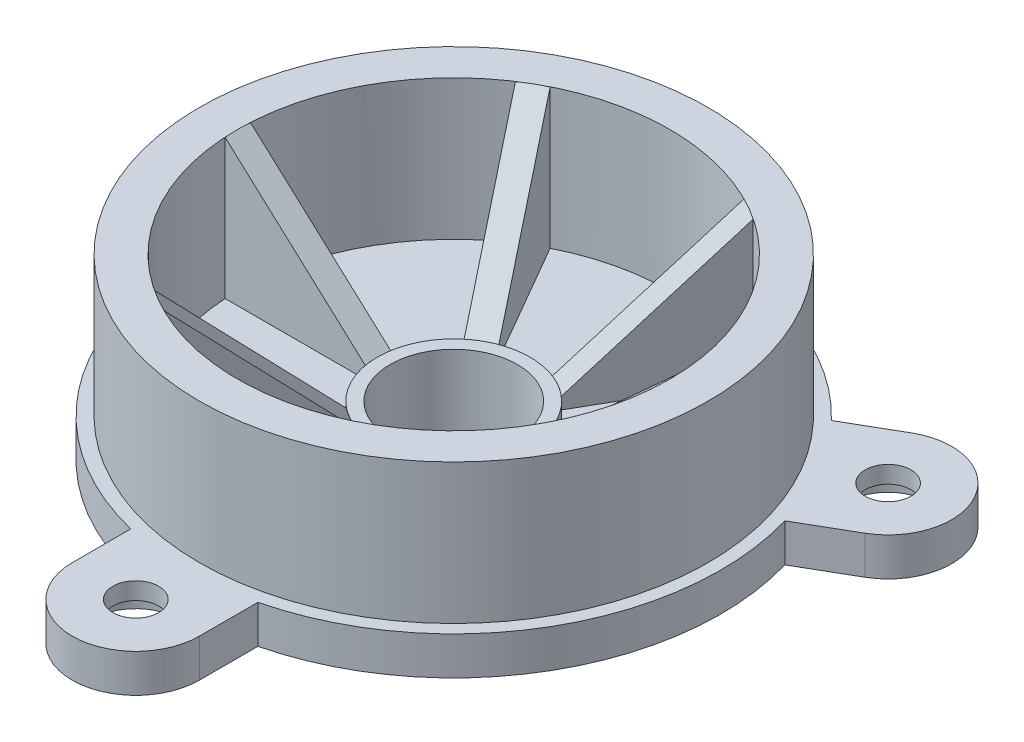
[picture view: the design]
ISO-10303-21;
HEADER;
FILE_DESCRIPTION(('STEP AP214'),'2;1');
FILE_NAME('part.step','',(''),(''),'','','');
FILE_SCHEMA(('AUTOMOTIVE_DESIGN { 1 0 10303 214 1 1 1 1 }'));
ENDSEC;
DATA;
#1=APPLICATION_CONTEXT('core data for automotive mechanical design processes');
#2=APPLICATION_PROTOCOL_DEFINITION('international standard','automotive_design',2000,#1);
#3=PRODUCT_CONTEXT('',#1,'mechanical');
#4=PRODUCT('Part','Part','',(#3));
#5=PRODUCT_RELATED_PRODUCT_CATEGORY('part','',(#4));
#6=PRODUCT_DEFINITION_FORMATION('','',#4);
#7=PRODUCT_DEFINITION_CONTEXT('part definition',#1,'design');
#8=PRODUCT_DEFINITION('design','',#6,#7);
#9=PRODUCT_DEFINITION_SHAPE('','',#8);
#10=(LENGTH_UNIT() NAMED_UNIT(*) SI_UNIT(.MILLI.,.METRE.));
#11=(NAMED_UNIT(*) PLANE_ANGLE_UNIT() SI_UNIT($,.RADIAN.));
#12=(NAMED_UNIT(*) SI_UNIT($,.STERADIAN.) SOLID_ANGLE_UNIT());
#13=UNCERTAINTY_MEASURE_WITH_UNIT(LENGTH_MEASURE(1.E-05),#10,'distance_accuracy_value','');
#14=(GEOMETRIC_REPRESENTATION_CONTEXT(3) GLOBAL_UNCERTAINTY_ASSIGNED_CONTEXT((#13)) GLOBAL_UNIT_ASSIGNED_CONTEXT((#10,
#11,#12)) REPRESENTATION_CONTEXT('',''));
#15=CARTESIAN_POINT('',(0.,0.,0.));
#16=DIRECTION('',(0.,0.,1.));
#17=DIRECTION('',(1.,0.,0.));
#18=AXIS2_PLACEMENT_3D('',#15,#16,#17);
#19=CARTESIAN_POINT('',(0.,91.9242942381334,0.));
#20=DIRECTION('',(0.,1.,0.));
#21=DIRECTION('',(0.,0.,1.));
#22=AXIS2_PLACEMENT_3D('',#19,#20,#21);
#23=CYLINDRICAL_SURFACE('',#22,6.00000000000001);
#24=CARTESIAN_POINT('',(0.,0.54545454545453,0.));
#25=DIRECTION('',(-0.336336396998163,-0.739940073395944,-0.582551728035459));
#26=DIRECTION('',(-0.369970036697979,0.672672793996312,-0.640806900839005));
#27=AXIS2_PLACEMENT_3D('',#24,#25,#26);
#28=ELLIPSE('',#27,8.10876477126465,6.00000000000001);
#29=CARTESIAN_POINT('',(-3.00000000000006,6.00000000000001,-5.1961524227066));
#30=VERTEX_POINT('',#29);
#31=CARTESIAN_POINT('',(-3.82406529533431,5.92370889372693,-4.62347538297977));
#32=VERTEX_POINT('',#31);
#33=EDGE_CURVE('E50',#30,#32,#28,.F.);
#34=ORIENTED_EDGE('',*,*,#33,.T.);
#35=DIRECTION('',(0.,1.,0.));
#36=VECTOR('',#35,1.);
#37=CARTESIAN_POINT('',(-3.82406529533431,91.9242942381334,-4.62347538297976));
#38=LINE('',#37,#36);
#39=CARTESIAN_POINT('',(-3.82406529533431,5.,-4.62347538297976));
#40=VERTEX_POINT('',#39);
#41=EDGE_CURVE('E341',#32,#40,#38,.F.);
#42=ORIENTED_EDGE('',*,*,#41,.T.);
#43=CARTESIAN_POINT('',(0.,5.,0.));
#44=DIRECTION('',(0.,1.,0.));
#45=DIRECTION('',(0.,0.,1.));
#46=AXIS2_PLACEMENT_3D('',#43,#44,#45);
#47=CIRCLE('',#46,6.00000000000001);
#48=CARTESIAN_POINT('',(-5.91607978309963,5.,-1.));
#49=VERTEX_POINT('',#48);
#50=EDGE_CURVE('E617',#40,#49,#47,.T.);
#51=ORIENTED_EDGE('',*,*,#50,.T.);
#52=DIRECTION('',(0.,1.,0.));
#53=VECTOR('',#52,1.);
#54=CARTESIAN_POINT('',(-5.91607978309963,91.9242942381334,-1.));
#55=LINE('',#54,#53);
#56=CARTESIAN_POINT('',(-5.91607978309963,5.92370889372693,-1.));
#57=VERTEX_POINT('',#56);
#58=EDGE_CURVE('E466',#57,#49,#55,.F.);
#59=ORIENTED_EDGE('',*,*,#58,.F.);
#60=CARTESIAN_POINT('',(0.,0.545454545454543,0.));
#61=DIRECTION('',(-0.672672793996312,-0.739940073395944,0.));
#62=DIRECTION('',(-0.739940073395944,0.672672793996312,0.));
#63=AXIS2_PLACEMENT_3D('',#60,#61,#62);
#64=ELLIPSE('',#63,8.10876477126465,6.00000000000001);
#65=CARTESIAN_POINT('',(-6.00000000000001,6.00000000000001,0.));
#66=VERTEX_POINT('',#65);
#67=EDGE_CURVE('E479',#57,#66,#64,.F.);
#68=ORIENTED_EDGE('',*,*,#67,.T.);
#69=CARTESIAN_POINT('',(0.,6.00000000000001,0.));
#70=DIRECTION('',(0.,1.,0.));
#71=DIRECTION('',(0.,0.,1.));
#72=AXIS2_PLACEMENT_3D('',#69,#70,#71);
#73=CIRCLE('',#72,6.00000000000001);
#74=EDGE_CURVE('E622',#30,#66,#73,.T.);
#75=ORIENTED_EDGE('',*,*,#74,.F.);
#76=EDGE_LOOP('',(#34,#42,#51,#59,#68,#75));
#77=FACE_BOUND('',#76,.T.);
#78=ADVANCED_FACE('F33',(#77),#23,.T.);
#79=CARTESIAN_POINT('',(0.,91.9242942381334,0.));
#80=DIRECTION('',(0.,1.,0.));
#81=DIRECTION('',(0.,0.,1.));
#82=AXIS2_PLACEMENT_3D('',#79,#80,#81);
#83=CYLINDRICAL_SURFACE('',#82,17.);
#84=CARTESIAN_POINT('',(0.,5.,0.));
#85=DIRECTION('',(0.,1.,0.));
#86=DIRECTION('',(0.,0.,1.));
#87=AXIS2_PLACEMENT_3D('',#84,#85,#86);
#88=CIRCLE('',#87,17.);
#89=CARTESIAN_POINT('',(-9.35130677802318,5.,-14.196938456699));
#90=VERTEX_POINT('',#89);
#91=CARTESIAN_POINT('',(-16.9705627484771,5.,-1.));
#92=VERTEX_POINT('',#91);
#93=EDGE_CURVE('E316',#90,#92,#88,.T.);
#94=ORIENTED_EDGE('',*,*,#93,.F.);
#95=DIRECTION('',(0.,1.,0.));
#96=VECTOR('',#95,1.);
#97=CARTESIAN_POINT('',(-9.35130677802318,91.9242942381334,-14.196938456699));
#98=LINE('',#97,#96);
#99=CARTESIAN_POINT('',(-9.35130677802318,15.973238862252,-14.196938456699));
#100=VERTEX_POINT('',#99);
#101=EDGE_CURVE('E339',#90,#100,#98,.T.);
#102=ORIENTED_EDGE('',*,*,#101,.T.);
#103=CARTESIAN_POINT('',(0.,0.54545454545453,0.));
#104=DIRECTION('',(-0.336336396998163,-0.739940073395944,-0.582551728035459));
#105=DIRECTION('',(-0.369970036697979,0.672672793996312,-0.640806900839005));
#106=AXIS2_PLACEMENT_3D('',#103,#104,#105);
#107=ELLIPSE('',#106,22.9748335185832,17.);
#108=CARTESIAN_POINT('',(-8.50000000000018,16.,-14.7224318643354));
#109=VERTEX_POINT('',#108);
#110=EDGE_CURVE('E343',#100,#109,#107,.T.);
#111=ORIENTED_EDGE('',*,*,#110,.T.);
#112=CARTESIAN_POINT('',(0.,16.,0.));
#113=DIRECTION('',(0.,1.,0.));
#114=DIRECTION('',(0.,0.,1.));
#115=AXIS2_PLACEMENT_3D('',#112,#113,#114);
#116=CIRCLE('',#115,17.);
#117=CARTESIAN_POINT('',(-17.,16.,0.));
#118=VERTEX_POINT('',#117);
#119=EDGE_CURVE('E610',#109,#118,#116,.T.);
#120=ORIENTED_EDGE('',*,*,#119,.T.);
#121=CARTESIAN_POINT('',(0.,0.545454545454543,0.));
#122=DIRECTION('',(-0.672672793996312,-0.739940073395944,0.));
#123=DIRECTION('',(-0.739940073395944,0.672672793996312,0.));
#124=AXIS2_PLACEMENT_3D('',#121,#122,#123);
#125=ELLIPSE('',#124,22.9748335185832,17.);
#126=CARTESIAN_POINT('',(-16.9705627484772,15.973238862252,-1.));
#127=VERTEX_POINT('',#126);
#128=EDGE_CURVE('E478',#118,#127,#125,.T.);
#129=ORIENTED_EDGE('',*,*,#128,.T.);
#130=DIRECTION('',(0.,1.,0.));
#131=VECTOR('',#130,1.);
#132=CARTESIAN_POINT('',(-16.9705627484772,91.9242942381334,-1.));
#133=LINE('',#132,#131);
#134=EDGE_CURVE('E457',#92,#127,#133,.T.);
#135=ORIENTED_EDGE('',*,*,#134,.F.);
#136=EDGE_LOOP('',(#94,#102,#111,#120,#129,#135));
#137=FACE_BOUND('',#136,.T.);
#138=ADVANCED_FACE('F655',(#137),#83,.F.);
#139=CARTESIAN_POINT('',(6.00000000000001,5.,0.));
#140=DIRECTION('',(0.,-1.,0.));
#141=DIRECTION('',(0.,0.,-1.));
#142=AXIS2_PLACEMENT_3D('',#139,#140,#141);
#143=PLANE('',#142);
#144=DIRECTION('',(-0.50000000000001,0.,-0.866025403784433));
#145=VECTOR('',#144,1.);
#146=CARTESIAN_POINT('',(2.3660254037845,5.,2.09807621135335));
#147=LINE('',#146,#145);
#148=CARTESIAN_POINT('',(-2.09201448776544,5.,-5.62347538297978));
#149=VERTEX_POINT('',#148);
#150=CARTESIAN_POINT('',(-7.61925597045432,5.,-15.196938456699));
#151=VERTEX_POINT('',#150);
#152=EDGE_CURVE('E310',#149,#151,#147,.T.);
#153=ORIENTED_EDGE('',*,*,#152,.F.);
#154=CARTESIAN_POINT('',(2.09201448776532,5.,-5.62347538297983));
#155=VERTEX_POINT('',#154);
#156=EDGE_CURVE('E738',#155,#149,#47,.T.);
#157=ORIENTED_EDGE('',*,*,#156,.F.);
#158=DIRECTION('',(0.499999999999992,0.,-0.866025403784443));
#159=VECTOR('',#158,1.);
#160=CARTESIAN_POINT('',(0.633974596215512,5.,-3.09807621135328));
#161=LINE('',#160,#159);
#162=CARTESIAN_POINT('',(7.619255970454,5.,-15.1969384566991));
#163=VERTEX_POINT('',#162);
#164=EDGE_CURVE('E312',#155,#163,#161,.T.);
#165=ORIENTED_EDGE('',*,*,#164,.T.);
#166=EDGE_CURVE('E305',#163,#151,#88,.T.);
#167=ORIENTED_EDGE('',*,*,#166,.T.);
#168=EDGE_LOOP('',(#153,#157,#165,#167));
#169=FACE_BOUND('',#168,.T.);
#170=ADVANCED_FACE('F307',(#169),#143,.F.);
#171=DIRECTION('',(0.,1.,0.));
#172=VECTOR('',#171,1.);
#173=CARTESIAN_POINT('',(-2.09201448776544,91.9242942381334,-5.62347538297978));
#174=LINE('',#173,#172);
#175=CARTESIAN_POINT('',(-2.09201448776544,5.92370889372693,-5.62347538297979));
#176=VERTEX_POINT('',#175);
#177=EDGE_CURVE('E58',#176,#149,#174,.F.);
#178=ORIENTED_EDGE('',*,*,#177,.F.);
#179=EDGE_CURVE('E345',#176,#30,#28,.F.);
#180=ORIENTED_EDGE('',*,*,#179,.T.);
#181=CARTESIAN_POINT('',(2.99999999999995,6.00000000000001,-5.19615242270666));
#182=VERTEX_POINT('',#181);
#183=EDGE_CURVE('E816',#182,#30,#73,.T.);
#184=ORIENTED_EDGE('',*,*,#183,.F.);
#185=CARTESIAN_POINT('',(0.,0.54545454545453,0.));
#186=DIRECTION('',(0.336336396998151,-0.739940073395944,-0.582551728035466));
#187=DIRECTION('',(0.369970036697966,0.672672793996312,-0.640806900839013));
#188=AXIS2_PLACEMENT_3D('',#185,#186,#187);
#189=ELLIPSE('',#188,8.10876477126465,6.00000000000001);
#190=CARTESIAN_POINT('',(2.09201448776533,5.92370889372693,-5.62347538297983));
#191=VERTEX_POINT('',#190);
#192=EDGE_CURVE('E372',#182,#191,#189,.F.);
#193=ORIENTED_EDGE('',*,*,#192,.T.);
#194=DIRECTION('',(0.,1.,0.));
#195=VECTOR('',#194,1.);
#196=CARTESIAN_POINT('',(2.09201448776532,91.9242942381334,-5.62347538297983));
#197=LINE('',#196,#195);
#198=EDGE_CURVE('E365',#191,#155,#197,.F.);
#199=ORIENTED_EDGE('',*,*,#198,.T.);
#200=ORIENTED_EDGE('',*,*,#156,.T.);
#201=EDGE_LOOP('',(#178,#180,#184,#193,#199,#200));
#202=FACE_BOUND('',#201,.T.);
#203=ADVANCED_FACE('F657',(#202),#23,.T.);
#204=CARTESIAN_POINT('',(8.49999999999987,16.,-14.7224318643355));
#205=VERTEX_POINT('',#204);
#206=EDGE_CURVE('E827',#205,#109,#116,.T.);
#207=ORIENTED_EDGE('',*,*,#206,.T.);
#208=CARTESIAN_POINT('',(-7.61925597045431,15.9732388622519,-15.196938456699));
#209=VERTEX_POINT('',#208);
#210=EDGE_CURVE('E323',#109,#209,#107,.T.);
#211=ORIENTED_EDGE('',*,*,#210,.T.);
#212=DIRECTION('',(0.,1.,0.));
#213=VECTOR('',#212,1.);
#214=CARTESIAN_POINT('',(-7.61925597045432,91.9242942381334,-15.196938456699));
#215=LINE('',#214,#213);
#216=EDGE_CURVE('E319',#151,#209,#215,.T.);
#217=ORIENTED_EDGE('',*,*,#216,.F.);
#218=ORIENTED_EDGE('',*,*,#166,.F.);
#219=DIRECTION('',(0.,1.,0.));
#220=VECTOR('',#219,1.);
#221=CARTESIAN_POINT('',(7.619255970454,91.9242942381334,-15.1969384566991));
#222=LINE('',#221,#220);
#223=CARTESIAN_POINT('',(7.619255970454,15.973238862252,-15.1969384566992));
#224=VERTEX_POINT('',#223);
#225=EDGE_CURVE('E363',#163,#224,#222,.T.);
#226=ORIENTED_EDGE('',*,*,#225,.T.);
#227=CARTESIAN_POINT('',(0.,0.54545454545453,0.));
#228=DIRECTION('',(0.336336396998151,-0.739940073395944,-0.582551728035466));
#229=DIRECTION('',(0.369970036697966,0.672672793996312,-0.640806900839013));
#230=AXIS2_PLACEMENT_3D('',#227,#228,#229);
#231=ELLIPSE('',#230,22.9748335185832,17.);
#232=EDGE_CURVE('E367',#224,#205,#231,.T.);
#233=ORIENTED_EDGE('',*,*,#232,.T.);
#234=EDGE_LOOP('',(#207,#211,#217,#218,#226,#233));
#235=FACE_BOUND('',#234,.T.);
#236=ADVANCED_FACE('F321',(#235),#83,.F.);
#237=DIRECTION('',(0.499999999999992,0.,-0.866025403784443));
#238=VECTOR('',#237,1.);
#239=CARTESIAN_POINT('',(2.3660254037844,5.,-2.0980762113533));
#240=LINE('',#239,#238);
#241=CARTESIAN_POINT('',(3.82406529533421,5.,-4.62347538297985));
#242=VERTEX_POINT('',#241);
#243=CARTESIAN_POINT('',(9.35130677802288,5.,-14.1969384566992));
#244=VERTEX_POINT('',#243);
#245=EDGE_CURVE('E350',#242,#244,#240,.T.);
#246=ORIENTED_EDGE('',*,*,#245,.F.);
#247=CARTESIAN_POINT('',(5.91607978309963,5.,-1.));
#248=VERTEX_POINT('',#247);
#249=EDGE_CURVE('E718',#248,#242,#47,.T.);
#250=ORIENTED_EDGE('',*,*,#249,.F.);
#251=DIRECTION('',(1.,0.,0.));
#252=VECTOR('',#251,1.);
#253=CARTESIAN_POINT('',(6.00000000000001,5.,-1.));
#254=LINE('',#253,#252);
#255=CARTESIAN_POINT('',(16.9705627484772,5.,-1.));
#256=VERTEX_POINT('',#255);
#257=EDGE_CURVE('E388',#248,#256,#254,.T.);
#258=ORIENTED_EDGE('',*,*,#257,.T.);
#259=EDGE_CURVE('E315',#256,#244,#88,.T.);
#260=ORIENTED_EDGE('',*,*,#259,.T.);
#261=EDGE_LOOP('',(#246,#250,#258,#260));
#262=FACE_BOUND('',#261,.T.);
#263=ADVANCED_FACE('F704',(#262),#143,.F.);
#264=DIRECTION('',(0.,1.,0.));
#265=VECTOR('',#264,1.);
#266=CARTESIAN_POINT('',(3.82406529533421,91.9242942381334,-4.62347538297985));
#267=LINE('',#266,#265);
#268=CARTESIAN_POINT('',(3.82406529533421,5.92370889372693,-4.62347538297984));
#269=VERTEX_POINT('',#268);
#270=EDGE_CURVE('E359',#269,#242,#267,.F.);
#271=ORIENTED_EDGE('',*,*,#270,.F.);
#272=EDGE_CURVE('E370',#269,#182,#189,.F.);
#273=ORIENTED_EDGE('',*,*,#272,.T.);
#274=CARTESIAN_POINT('',(6.,6.00000000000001,0.));
#275=VERTEX_POINT('',#274);
#276=EDGE_CURVE('E815',#275,#182,#73,.T.);
#277=ORIENTED_EDGE('',*,*,#276,.F.);
#278=CARTESIAN_POINT('',(0.,0.545454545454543,0.));
#279=DIRECTION('',(0.672672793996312,-0.739940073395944,0.));
#280=DIRECTION('',(0.739940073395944,0.672672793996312,0.));
#281=AXIS2_PLACEMENT_3D('',#278,#279,#280);
#282=ELLIPSE('',#281,8.10876477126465,6.00000000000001);
#283=CARTESIAN_POINT('',(5.91607978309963,5.92370889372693,-1.));
#284=VERTEX_POINT('',#283);
#285=EDGE_CURVE('E399',#275,#284,#282,.F.);
#286=ORIENTED_EDGE('',*,*,#285,.T.);
#287=DIRECTION('',(0.,1.,0.));
#288=VECTOR('',#287,1.);
#289=CARTESIAN_POINT('',(5.91607978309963,91.9242942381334,-1.));
#290=LINE('',#289,#288);
#291=EDGE_CURVE('E392',#284,#248,#290,.F.);
#292=ORIENTED_EDGE('',*,*,#291,.T.);
#293=ORIENTED_EDGE('',*,*,#249,.T.);
#294=EDGE_LOOP('',(#271,#273,#277,#286,#292,#293));
#295=FACE_BOUND('',#294,.T.);
#296=ADVANCED_FACE('F668',(#295),#23,.T.);
#297=CARTESIAN_POINT('',(17.,16.,0.));
#298=VERTEX_POINT('',#297);
#299=EDGE_CURVE('E731',#298,#205,#116,.T.);
#300=ORIENTED_EDGE('',*,*,#299,.T.);
#301=CARTESIAN_POINT('',(9.35130677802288,15.973238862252,-14.1969384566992));
#302=VERTEX_POINT('',#301);
#303=EDGE_CURVE('E369',#205,#302,#231,.T.);
#304=ORIENTED_EDGE('',*,*,#303,.T.);
#305=DIRECTION('',(0.,1.,0.));
#306=VECTOR('',#305,1.);
#307=CARTESIAN_POINT('',(9.35130677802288,91.9242942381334,-14.1969384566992));
#308=LINE('',#307,#306);
#309=EDGE_CURVE('E356',#244,#302,#308,.T.);
#310=ORIENTED_EDGE('',*,*,#309,.F.);
#311=ORIENTED_EDGE('',*,*,#259,.F.);
#312=DIRECTION('',(0.,1.,0.));
#313=VECTOR('',#312,1.);
#314=CARTESIAN_POINT('',(16.9705627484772,91.9242942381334,-1.));
#315=LINE('',#314,#313);
#316=CARTESIAN_POINT('',(16.9705627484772,15.9732388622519,-1.));
#317=VERTEX_POINT('',#316);
#318=EDGE_CURVE('E390',#256,#317,#315,.T.);
#319=ORIENTED_EDGE('',*,*,#318,.T.);
#320=CARTESIAN_POINT('',(0.,0.545454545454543,0.));
#321=DIRECTION('',(0.672672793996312,-0.739940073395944,0.));
#322=DIRECTION('',(0.739940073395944,0.672672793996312,0.));
#323=AXIS2_PLACEMENT_3D('',#320,#321,#322);
#324=ELLIPSE('',#323,22.9748335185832,17.);
#325=EDGE_CURVE('E394',#317,#298,#324,.T.);
#326=ORIENTED_EDGE('',*,*,#325,.T.);
#327=EDGE_LOOP('',(#300,#304,#310,#311,#319,#326));
#328=FACE_BOUND('',#327,.T.);
#329=ADVANCED_FACE('F702',(#328),#83,.F.);
#330=DIRECTION('',(1.,0.,0.));
#331=VECTOR('',#330,1.);
#332=CARTESIAN_POINT('',(6.00000000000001,5.,1.));
#333=LINE('',#332,#331);
#334=CARTESIAN_POINT('',(5.91607978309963,5.,1.));
#335=VERTEX_POINT('',#334);
#336=CARTESIAN_POINT('',(16.9705627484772,5.,1.));
#337=VERTEX_POINT('',#336);
#338=EDGE_CURVE('E376',#335,#337,#333,.T.);
#339=ORIENTED_EDGE('',*,*,#338,.F.);
#340=CARTESIAN_POINT('',(3.82406529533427,5.,4.62347538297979));
#341=VERTEX_POINT('',#340);
#342=EDGE_CURVE('E739',#341,#335,#47,.T.);
#343=ORIENTED_EDGE('',*,*,#342,.F.);
#344=DIRECTION('',(0.500000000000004,0.,0.866025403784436));
#345=VECTOR('',#344,1.);
#346=CARTESIAN_POINT('',(2.36602540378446,5.,2.09807621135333));
#347=LINE('',#346,#345);
#348=CARTESIAN_POINT('',(9.35130677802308,5.,14.196938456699));
#349=VERTEX_POINT('',#348);
#350=EDGE_CURVE('E415',#341,#349,#347,.T.);
#351=ORIENTED_EDGE('',*,*,#350,.T.);
#352=EDGE_CURVE('E780',#349,#337,#88,.T.);
#353=ORIENTED_EDGE('',*,*,#352,.T.);
#354=EDGE_LOOP('',(#339,#343,#351,#353));
#355=FACE_BOUND('',#354,.T.);
#356=ADVANCED_FACE('F694',(#355),#143,.F.);
#357=DIRECTION('',(0.,1.,0.));
#358=VECTOR('',#357,1.);
#359=CARTESIAN_POINT('',(5.91607978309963,91.9242942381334,1.));
#360=LINE('',#359,#358);
#361=CARTESIAN_POINT('',(5.91607978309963,5.92370889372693,1.));
#362=VERTEX_POINT('',#361);
#363=EDGE_CURVE('E385',#362,#335,#360,.F.);
#364=ORIENTED_EDGE('',*,*,#363,.F.);
#365=EDGE_CURVE('E397',#362,#275,#282,.F.);
#366=ORIENTED_EDGE('',*,*,#365,.T.);
#367=CARTESIAN_POINT('',(3.00000000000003,6.00000000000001,5.19615242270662));
#368=VERTEX_POINT('',#367);
#369=EDGE_CURVE('E813',#368,#275,#73,.T.);
#370=ORIENTED_EDGE('',*,*,#369,.F.);
#371=CARTESIAN_POINT('',(0.,0.545454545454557,0.));
#372=DIRECTION('',(0.336336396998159,-0.739940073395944,0.582551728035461));
#373=DIRECTION('',(0.369970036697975,0.672672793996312,0.640806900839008));
#374=AXIS2_PLACEMENT_3D('',#371,#372,#373);
#375=ELLIPSE('',#374,8.10876477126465,6.00000000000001);
#376=CARTESIAN_POINT('',(3.82406529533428,5.92370889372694,4.6234753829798));
#377=VERTEX_POINT('',#376);
#378=EDGE_CURVE('E426',#368,#377,#375,.F.);
#379=ORIENTED_EDGE('',*,*,#378,.T.);
#380=DIRECTION('',(0.,1.,0.));
#381=VECTOR('',#380,1.);
#382=CARTESIAN_POINT('',(3.82406529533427,91.9242942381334,4.62347538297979));
#383=LINE('',#382,#381);
#384=EDGE_CURVE('E419',#377,#341,#383,.F.);
#385=ORIENTED_EDGE('',*,*,#384,.T.);
#386=ORIENTED_EDGE('',*,*,#342,.T.);
#387=EDGE_LOOP('',(#364,#366,#370,#379,#385,#386));
#388=FACE_BOUND('',#387,.T.);
#389=ADVANCED_FACE('F685',(#388),#23,.T.);
#390=CARTESIAN_POINT('',(8.50000000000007,16.,14.7224318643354));
#391=VERTEX_POINT('',#390);
#392=EDGE_CURVE('E797',#391,#298,#116,.T.);
#393=ORIENTED_EDGE('',*,*,#392,.T.);
#394=CARTESIAN_POINT('',(16.9705627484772,15.973238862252,1.));
#395=VERTEX_POINT('',#394);
#396=EDGE_CURVE('E396',#298,#395,#324,.T.);
#397=ORIENTED_EDGE('',*,*,#396,.T.);
#398=DIRECTION('',(0.,1.,0.));
#399=VECTOR('',#398,1.);
#400=CARTESIAN_POINT('',(16.9705627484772,91.9242942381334,1.));
#401=LINE('',#400,#399);
#402=EDGE_CURVE('E382',#337,#395,#401,.T.);
#403=ORIENTED_EDGE('',*,*,#402,.F.);
#404=ORIENTED_EDGE('',*,*,#352,.F.);
#405=DIRECTION('',(0.,1.,0.));
#406=VECTOR('',#405,1.);
#407=CARTESIAN_POINT('',(9.35130677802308,91.9242942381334,14.196938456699));
#408=LINE('',#407,#406);
#409=CARTESIAN_POINT('',(9.35130677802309,15.973238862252,14.196938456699));
#410=VERTEX_POINT('',#409);
#411=EDGE_CURVE('E417',#349,#410,#408,.T.);
#412=ORIENTED_EDGE('',*,*,#411,.T.);
#413=CARTESIAN_POINT('',(0.,0.545454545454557,0.));
#414=DIRECTION('',(0.336336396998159,-0.739940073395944,0.582551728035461));
#415=DIRECTION('',(0.369970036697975,0.672672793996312,0.640806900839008));
#416=AXIS2_PLACEMENT_3D('',#413,#414,#415);
#417=ELLIPSE('',#416,22.9748335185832,17.);
#418=EDGE_CURVE('E421',#410,#391,#417,.T.);
#419=ORIENTED_EDGE('',*,*,#418,.T.);
#420=EDGE_LOOP('',(#393,#397,#403,#404,#412,#419));
#421=FACE_BOUND('',#420,.T.);
#422=ADVANCED_FACE('F692',(#421),#83,.F.);
#423=DIRECTION('',(0.500000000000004,0.,0.866025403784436));
#424=VECTOR('',#423,1.);
#425=CARTESIAN_POINT('',(0.633974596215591,5.,3.09807621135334));
#426=LINE('',#425,#424);
#427=CARTESIAN_POINT('',(2.0920144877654,5.,5.6234753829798));
#428=VERTEX_POINT('',#427);
#429=CARTESIAN_POINT('',(7.61925597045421,5.,15.196938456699));
#430=VERTEX_POINT('',#429);
#431=EDGE_CURVE('E403',#428,#430,#426,.T.);
#432=ORIENTED_EDGE('',*,*,#431,.F.);
#433=CARTESIAN_POINT('',(-2.09201448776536,5.,5.62347538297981));
#434=VERTEX_POINT('',#433);
#435=EDGE_CURVE('E623',#434,#428,#47,.T.);
#436=ORIENTED_EDGE('',*,*,#435,.F.);
#437=DIRECTION('',(-0.499999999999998,0.,0.86602540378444));
#438=VECTOR('',#437,1.);
#439=CARTESIAN_POINT('',(2.36602540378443,5.,-2.09807621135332));
#440=LINE('',#439,#438);
#441=CARTESIAN_POINT('',(-7.6192559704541,5.,15.1969384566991));
#442=VERTEX_POINT('',#441);
#443=EDGE_CURVE('E444',#434,#442,#440,.T.);
#444=ORIENTED_EDGE('',*,*,#443,.T.);
#445=EDGE_CURVE('E618',#442,#430,#88,.T.);
#446=ORIENTED_EDGE('',*,*,#445,.T.);
#447=EDGE_LOOP('',(#432,#436,#444,#446));
#448=FACE_BOUND('',#447,.T.);
#449=ADVANCED_FACE('F683',(#448),#143,.F.);
#450=DIRECTION('',(0.,1.,0.));
#451=VECTOR('',#450,1.);
#452=CARTESIAN_POINT('',(2.0920144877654,91.9242942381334,5.6234753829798));
#453=LINE('',#452,#451);
#454=CARTESIAN_POINT('',(2.0920144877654,5.92370889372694,5.6234753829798));
#455=VERTEX_POINT('',#454);
#456=EDGE_CURVE('E412',#455,#428,#453,.F.);
#457=ORIENTED_EDGE('',*,*,#456,.F.);
#458=EDGE_CURVE('E424',#455,#368,#375,.F.);
#459=ORIENTED_EDGE('',*,*,#458,.T.);
#460=CARTESIAN_POINT('',(-2.99999999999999,6.,5.19615242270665));
#461=VERTEX_POINT('',#460);
#462=EDGE_CURVE('E627',#461,#368,#73,.T.);
#463=ORIENTED_EDGE('',*,*,#462,.F.);
#464=CARTESIAN_POINT('',(0.,0.54545454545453,0.));
#465=DIRECTION('',(-0.336336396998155,-0.739940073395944,0.582551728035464));
#466=DIRECTION('',(-0.36997003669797,0.672672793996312,0.64080690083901));
#467=AXIS2_PLACEMENT_3D('',#464,#465,#466);
#468=ELLIPSE('',#467,8.10876477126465,6.00000000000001);
#469=CARTESIAN_POINT('',(-2.09201448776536,5.92370889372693,5.62347538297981));
#470=VERTEX_POINT('',#469);
#471=EDGE_CURVE('E453',#461,#470,#468,.F.);
#472=ORIENTED_EDGE('',*,*,#471,.T.);
#473=DIRECTION('',(0.,1.,0.));
#474=VECTOR('',#473,1.);
#475=CARTESIAN_POINT('',(-2.09201448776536,91.9242942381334,5.62347538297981));
#476=LINE('',#475,#474);
#477=EDGE_CURVE('E446',#470,#434,#476,.F.);
#478=ORIENTED_EDGE('',*,*,#477,.T.);
#479=ORIENTED_EDGE('',*,*,#435,.T.);
#480=EDGE_LOOP('',(#457,#459,#463,#472,#478,#479));
#481=FACE_BOUND('',#480,.T.);
#482=ADVANCED_FACE('F673',(#481),#23,.T.);
#483=DIRECTION('',(-0.499999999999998,0.,0.86602540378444));
#484=VECTOR('',#483,1.);
#485=CARTESIAN_POINT('',(0.633974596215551,5.,-3.09807621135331));
#486=LINE('',#485,#484);
#487=CARTESIAN_POINT('',(-3.82406529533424,5.,4.62347538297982));
#488=VERTEX_POINT('',#487);
#489=CARTESIAN_POINT('',(-9.35130677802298,5.,14.1969384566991));
#490=VERTEX_POINT('',#489);
#491=EDGE_CURVE('E436',#488,#490,#486,.T.);
#492=ORIENTED_EDGE('',*,*,#491,.F.);
#493=CARTESIAN_POINT('',(-5.91607978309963,5.,1.));
#494=VERTEX_POINT('',#493);
#495=EDGE_CURVE('E619',#494,#488,#47,.T.);
#496=ORIENTED_EDGE('',*,*,#495,.F.);
#497=DIRECTION('',(-1.,0.,0.));
#498=VECTOR('',#497,1.);
#499=CARTESIAN_POINT('',(6.00000000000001,5.,1.));
#500=LINE('',#499,#498);
#501=CARTESIAN_POINT('',(-16.9705627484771,5.,1.));
#502=VERTEX_POINT('',#501);
#503=EDGE_CURVE('E471',#494,#502,#500,.T.);
#504=ORIENTED_EDGE('',*,*,#503,.T.);
#505=EDGE_CURVE('E614',#502,#490,#88,.T.);
#506=ORIENTED_EDGE('',*,*,#505,.T.);
#507=EDGE_LOOP('',(#492,#496,#504,#506));
#508=FACE_BOUND('',#507,.T.);
#509=ADVANCED_FACE('F679',(#508),#143,.F.);
#510=CARTESIAN_POINT('',(-8.49999999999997,16.,14.7224318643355));
#511=VERTEX_POINT('',#510);
#512=EDGE_CURVE('E613',#511,#391,#116,.T.);
#513=ORIENTED_EDGE('',*,*,#512,.T.);
#514=CARTESIAN_POINT('',(7.61925597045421,15.9732388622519,15.196938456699));
#515=VERTEX_POINT('',#514);
#516=EDGE_CURVE('E423',#391,#515,#417,.T.);
#517=ORIENTED_EDGE('',*,*,#516,.T.);
#518=DIRECTION('',(0.,1.,0.));
#519=VECTOR('',#518,1.);
#520=CARTESIAN_POINT('',(7.61925597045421,91.9242942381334,15.196938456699));
#521=LINE('',#520,#519);
#522=EDGE_CURVE('E409',#430,#515,#521,.T.);
#523=ORIENTED_EDGE('',*,*,#522,.F.);
#524=ORIENTED_EDGE('',*,*,#445,.F.);
#525=DIRECTION('',(0.,1.,0.));
#526=VECTOR('',#525,1.);
#527=CARTESIAN_POINT('',(-7.6192559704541,91.9242942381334,15.1969384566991));
#528=LINE('',#527,#526);
#529=CARTESIAN_POINT('',(-7.6192559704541,15.9732388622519,15.1969384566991));
#530=VERTEX_POINT('',#529);
#531=EDGE_CURVE('E442',#442,#530,#528,.T.);
#532=ORIENTED_EDGE('',*,*,#531,.T.);
#533=CARTESIAN_POINT('',(0.,0.54545454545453,0.));
#534=DIRECTION('',(-0.336336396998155,-0.739940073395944,0.582551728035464));
#535=DIRECTION('',(-0.36997003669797,0.672672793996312,0.64080690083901));
#536=AXIS2_PLACEMENT_3D('',#533,#534,#535);
#537=ELLIPSE('',#536,22.9748335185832,17.);
#538=EDGE_CURVE('E448',#530,#511,#537,.T.);
#539=ORIENTED_EDGE('',*,*,#538,.T.);
#540=EDGE_LOOP('',(#513,#517,#523,#524,#532,#539));
#541=FACE_BOUND('',#540,.T.);
#542=ADVANCED_FACE('F690',(#541),#83,.F.);
#543=CARTESIAN_POINT('',(21.,2.,0.));
#544=DIRECTION('',(0.,1.,0.));
#545=DIRECTION('',(0.,0.,1.));
#546=AXIS2_PLACEMENT_3D('',#543,#544,#545);
#547=PLANE('',#546);
#548=CARTESIAN_POINT('',(0.,2.,0.));
#549=DIRECTION('',(0.,1.,0.));
#550=DIRECTION('',(0.,0.,1.));
#551=AXIS2_PLACEMENT_3D('',#548,#549,#550);
#552=CIRCLE('',#551,10.);
#553=CARTESIAN_POINT('',(0.,2.,10.));
#554=VERTEX_POINT('',#553);
#555=EDGE_CURVE('E593',#554,#554,#552,.T.);
#556=ORIENTED_EDGE('',*,*,#555,.T.);
#557=EDGE_LOOP('',(#556));
#558=FACE_BOUND('',#557,.T.);
#559=CARTESIAN_POINT('',(0.,2.,25.));
#560=DIRECTION('',(0.,-1.,0.));
#561=DIRECTION('',(0.,0.,-1.));
#562=AXIS2_PLACEMENT_3D('',#559,#560,#561);
#563=CIRCLE('',#562,3.35);
#564=CARTESIAN_POINT('',(0.,2.,21.65));
#565=VERTEX_POINT('',#564);
#566=EDGE_CURVE('E554',#565,#565,#563,.T.);
#567=ORIENTED_EDGE('',*,*,#566,.F.);
#568=EDGE_LOOP('',(#567));
#569=FACE_BOUND('',#568,.T.);
#570=DIRECTION('',(0.866025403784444,0.,0.499999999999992));
#571=VECTOR('',#570,1.);
#572=CARTESIAN_POINT('',(-14.2705098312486,2.,-14.0125853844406));
#573=LINE('',#572,#571);
#574=CARTESIAN_POINT('',(-19.1506350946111,2.,-16.830127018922));
#575=VERTEX_POINT('',#574);
#576=CARTESIAN_POINT('',(-15.1635217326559,2.,-14.5281660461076));
#577=VERTEX_POINT('',#576);
#578=EDGE_CURVE('E507',#575,#577,#573,.T.);
#579=ORIENTED_EDGE('',*,*,#578,.T.);
#580=CARTESIAN_POINT('',(0.,2.,0.));
#581=DIRECTION('',(0.,1.,0.));
#582=DIRECTION('',(0.,0.,1.));
#583=AXIS2_PLACEMENT_3D('',#580,#581,#582);
#584=CIRCLE('',#583,21.);
#585=CARTESIAN_POINT('',(15.1635217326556,2.,-14.5281660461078));
#586=VERTEX_POINT('',#585);
#587=EDGE_CURVE('E600',#586,#577,#584,.T.);
#588=ORIENTED_EDGE('',*,*,#587,.F.);
#589=DIRECTION('',(0.866025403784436,0.,-0.500000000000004));
#590=VECTOR('',#589,1.);
#591=CARTESIAN_POINT('',(19.1506350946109,2.,-16.8301270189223));
#592=LINE('',#591,#590);
#593=CARTESIAN_POINT('',(19.1506350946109,2.,-16.8301270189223));
#594=VERTEX_POINT('',#593);
#595=EDGE_CURVE('E531',#586,#594,#592,.T.);
#596=ORIENTED_EDGE('',*,*,#595,.T.);
#597=CARTESIAN_POINT('',(21.6506350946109,2.,-12.5000000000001));
#598=DIRECTION('',(0.,1.,0.));
#599=DIRECTION('',(0.,0.,1.));
#600=AXIS2_PLACEMENT_3D('',#597,#598,#599);
#601=CIRCLE('',#600,5.);
#602=CARTESIAN_POINT('',(24.1506350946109,2.,-8.16987298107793));
#603=VERTEX_POINT('',#602);
#604=EDGE_CURVE('E529',#594,#603,#601,.F.);
#605=ORIENTED_EDGE('',*,*,#604,.T.);
#606=DIRECTION('',(-0.866025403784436,0.,0.500000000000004));
#607=VECTOR('',#606,1.);
#608=CARTESIAN_POINT('',(19.2705098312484,2.,-5.35233134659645));
#609=LINE('',#608,#607);
#610=CARTESIAN_POINT('',(20.1635217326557,2.,-5.86791200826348));
#611=VERTEX_POINT('',#610);
#612=EDGE_CURVE('E534',#603,#611,#609,.T.);
#613=ORIENTED_EDGE('',*,*,#612,.T.);
#614=CARTESIAN_POINT('',(5.,2.,20.3960780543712));
#615=VERTEX_POINT('',#614);
#616=EDGE_CURVE('E597',#615,#611,#584,.T.);
#617=ORIENTED_EDGE('',*,*,#616,.F.);
#618=DIRECTION('',(0.,0.,1.));
#619=VECTOR('',#618,1.);
#620=CARTESIAN_POINT('',(5.,2.,25.));
#621=LINE('',#620,#619);
#622=CARTESIAN_POINT('',(5.,2.,25.));
#623=VERTEX_POINT('',#622);
#624=EDGE_CURVE('E566',#615,#623,#621,.T.);
#625=ORIENTED_EDGE('',*,*,#624,.T.);
#626=CARTESIAN_POINT('',(0.,2.,25.));
#627=DIRECTION('',(0.,1.,0.));
#628=DIRECTION('',(0.,0.,1.));
#629=AXIS2_PLACEMENT_3D('',#626,#627,#628);
#630=CIRCLE('',#629,5.);
#631=CARTESIAN_POINT('',(-4.99999999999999,2.,25.));
#632=VERTEX_POINT('',#631);
#633=EDGE_CURVE('E564',#623,#632,#630,.F.);
#634=ORIENTED_EDGE('',*,*,#633,.T.);
#635=DIRECTION('',(0.,0.,-1.));
#636=VECTOR('',#635,1.);
#637=CARTESIAN_POINT('',(-5.,2.,19.3649167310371));
#638=LINE('',#637,#636);
#639=CARTESIAN_POINT('',(-5.,2.,20.3960780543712));
#640=VERTEX_POINT('',#639);
#641=EDGE_CURVE('E569',#632,#640,#638,.T.);
#642=ORIENTED_EDGE('',*,*,#641,.T.);
#643=CARTESIAN_POINT('',(-20.1635217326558,2.,-5.8679120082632));
#644=VERTEX_POINT('',#643);
#645=EDGE_CURVE('E596',#644,#640,#584,.T.);
#646=ORIENTED_EDGE('',*,*,#645,.F.);
#647=DIRECTION('',(-0.866025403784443,0.,-0.499999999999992));
#648=VECTOR('',#647,1.);
#649=CARTESIAN_POINT('',(-24.150635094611,2.,-8.16987298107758));
#650=LINE('',#649,#648);
#651=CARTESIAN_POINT('',(-24.150635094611,2.,-8.16987298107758));
#652=VERTEX_POINT('',#651);
#653=EDGE_CURVE('E504',#644,#652,#650,.T.);
#654=ORIENTED_EDGE('',*,*,#653,.T.);
#655=CARTESIAN_POINT('',(-21.6506350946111,2.,-12.4999999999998));
#656=DIRECTION('',(0.,1.,0.));
#657=DIRECTION('',(0.,0.,1.));
#658=AXIS2_PLACEMENT_3D('',#655,#656,#657);
#659=CIRCLE('',#658,5.);
#660=EDGE_CURVE('E502',#652,#575,#659,.F.);
#661=ORIENTED_EDGE('',*,*,#660,.T.);
#662=EDGE_LOOP('',(#579,#588,#596,#605,#613,#617,#625,#634,#642,#646,#654,#661));
#663=FACE_BOUND('',#662,.T.);
#664=CARTESIAN_POINT('',(21.6506350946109,2.,-12.5000000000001));
#665=DIRECTION('',(0.,-1.,0.));
#666=DIRECTION('',(0.,0.,-1.));
#667=AXIS2_PLACEMENT_3D('',#664,#665,#666);
#668=CIRCLE('',#667,3.35);
#669=CARTESIAN_POINT('',(21.6506350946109,2.,-15.8500000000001));
#670=VERTEX_POINT('',#669);
#671=EDGE_CURVE('E492',#670,#670,#668,.T.);
#672=ORIENTED_EDGE('',*,*,#671,.F.);
#673=EDGE_LOOP('',(#672));
#674=FACE_BOUND('',#673,.T.);
#675=CARTESIAN_POINT('',(-21.6506350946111,2.,-12.4999999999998));
#676=DIRECTION('',(0.,-1.,0.));
#677=DIRECTION('',(0.,0.,-1.));
#678=AXIS2_PLACEMENT_3D('',#675,#676,#677);
#679=CIRCLE('',#678,3.35);
#680=CARTESIAN_POINT('',(-21.6506350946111,2.,-15.8499999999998));
#681=VERTEX_POINT('',#680);
#682=EDGE_CURVE('E483',#681,#681,#679,.T.);
#683=ORIENTED_EDGE('',*,*,#682,.F.);
#684=EDGE_LOOP('',(#683));
#685=FACE_BOUND('',#684,.T.);
#686=ADVANCED_FACE('F873',(#558,#569,#663,#674,#685),#547,.F.);
#687=CARTESIAN_POINT('',(0.,91.9242942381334,0.));
#688=DIRECTION('',(0.,1.,0.));
#689=DIRECTION('',(0.,0.,1.));
#690=AXIS2_PLACEMENT_3D('',#687,#688,#689);
#691=CYLINDRICAL_SURFACE('',#690,21.);
#692=DIRECTION('',(0.,1.,0.));
#693=VECTOR('',#692,1.);
#694=CARTESIAN_POINT('',(-5.,91.9242942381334,20.3960780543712));
#695=LINE('',#694,#693);
#696=CARTESIAN_POINT('',(-4.99999999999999,5.,20.3960780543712));
#697=VERTEX_POINT('',#696);
#698=EDGE_CURVE('E584',#640,#697,#695,.T.);
#699=ORIENTED_EDGE('',*,*,#698,.T.);
#700=CARTESIAN_POINT('',(0.,5.,0.));
#701=DIRECTION('',(0.,1.,0.));
#702=DIRECTION('',(0.,0.,1.));
#703=AXIS2_PLACEMENT_3D('',#700,#701,#702);
#704=CIRCLE('',#703,21.);
#705=CARTESIAN_POINT('',(-20.1635217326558,5.,-5.86791200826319));
#706=VERTEX_POINT('',#705);
#707=EDGE_CURVE('E599',#706,#697,#704,.T.);
#708=ORIENTED_EDGE('',*,*,#707,.F.);
#709=DIRECTION('',(0.,1.,0.));
#710=VECTOR('',#709,1.);
#711=CARTESIAN_POINT('',(-20.1635217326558,91.9242942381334,-5.8679120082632));
#712=LINE('',#711,#710);
#713=EDGE_CURVE('E525',#706,#644,#712,.F.);
#714=ORIENTED_EDGE('',*,*,#713,.T.);
#715=ORIENTED_EDGE('',*,*,#645,.T.);
#716=EDGE_LOOP('',(#699,#708,#714,#715));
#717=FACE_BOUND('',#716,.T.);
#718=ADVANCED_FACE('F876',(#717),#691,.T.);
#719=DIRECTION('',(0.,1.,0.));
#720=VECTOR('',#719,1.);
#721=CARTESIAN_POINT('',(-15.1635217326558,91.9242942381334,-14.5281660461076));
#722=LINE('',#721,#720);
#723=CARTESIAN_POINT('',(-15.1635217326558,5.,-14.5281660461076));
#724=VERTEX_POINT('',#723);
#725=EDGE_CURVE('E522',#577,#724,#722,.T.);
#726=ORIENTED_EDGE('',*,*,#725,.T.);
#727=CARTESIAN_POINT('',(15.1635217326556,5.,-14.5281660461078));
#728=VERTEX_POINT('',#727);
#729=EDGE_CURVE('E604',#728,#724,#704,.T.);
#730=ORIENTED_EDGE('',*,*,#729,.F.);
#731=DIRECTION('',(0.,1.,0.));
#732=VECTOR('',#731,1.);
#733=CARTESIAN_POINT('',(15.1635217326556,91.9242942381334,-14.5281660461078));
#734=LINE('',#733,#732);
#735=EDGE_CURVE('E551',#728,#586,#734,.F.);
#736=ORIENTED_EDGE('',*,*,#735,.T.);
#737=ORIENTED_EDGE('',*,*,#587,.T.);
#738=EDGE_LOOP('',(#726,#730,#736,#737));
#739=FACE_BOUND('',#738,.T.);
#740=ADVANCED_FACE('F885',(#739),#691,.T.);
#741=CARTESIAN_POINT('',(10.,0.,0.));
#742=DIRECTION('',(0.,1.,0.));
#743=DIRECTION('',(0.,0.,1.));
#744=AXIS2_PLACEMENT_3D('',#741,#742,#743);
#745=PLANE('',#744);
#746=CARTESIAN_POINT('',(0.,0.,0.));
#747=DIRECTION('',(0.,1.,0.));
#748=DIRECTION('',(0.,0.,1.));
#749=AXIS2_PLACEMENT_3D('',#746,#747,#748);
#750=CIRCLE('',#749,5.00000000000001);
#751=CARTESIAN_POINT('',(0.,0.,5.00000000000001));
#752=VERTEX_POINT('',#751);
#753=EDGE_CURVE('E11',#752,#752,#750,.T.);
#754=ORIENTED_EDGE('',*,*,#753,.T.);
#755=EDGE_LOOP('',(#754));
#756=FACE_BOUND('',#755,.T.);
#757=CARTESIAN_POINT('',(0.,0.,0.));
#758=DIRECTION('',(0.,1.,0.));
#759=DIRECTION('',(0.,0.,1.));
#760=AXIS2_PLACEMENT_3D('',#757,#758,#759);
#761=CIRCLE('',#760,10.);
#762=CARTESIAN_POINT('',(0.,0.,10.));
#763=VERTEX_POINT('',#762);
#764=EDGE_CURVE('E590',#763,#763,#761,.T.);
#765=ORIENTED_EDGE('',*,*,#764,.F.);
#766=EDGE_LOOP('',(#765));
#767=FACE_BOUND('',#766,.T.);
#768=ADVANCED_FACE('F35',(#756,#767),#745,.F.);
#769=CARTESIAN_POINT('',(0.,91.9242942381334,0.));
#770=DIRECTION('',(0.,1.,0.));
#771=DIRECTION('',(0.,0.,1.));
#772=AXIS2_PLACEMENT_3D('',#769,#770,#771);
#773=CYLINDRICAL_SURFACE('',#772,5.00000000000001);
#774=ORIENTED_EDGE('',*,*,#753,.F.);
#775=EDGE_LOOP('',(#774));
#776=FACE_BOUND('',#775,.T.);
#777=CARTESIAN_POINT('',(0.,5.99999999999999,0.));
#778=DIRECTION('',(0.,1.,0.));
#779=DIRECTION('',(0.,0.,1.));
#780=AXIS2_PLACEMENT_3D('',#777,#778,#779);
#781=CIRCLE('',#780,5.00000000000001);
#782=CARTESIAN_POINT('',(0.,5.99999999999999,5.00000000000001));
#783=VERTEX_POINT('',#782);
#784=EDGE_CURVE('E42',#783,#783,#781,.T.);
#785=ORIENTED_EDGE('',*,*,#784,.T.);
#786=EDGE_LOOP('',(#785));
#787=FACE_BOUND('',#786,.T.);
#788=ADVANCED_FACE('F680',(#776,#787),#773,.F.);
#789=CARTESIAN_POINT('',(5.00000000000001,6.,0.));
#790=DIRECTION('',(0.,-1.,0.));
#791=DIRECTION('',(0.,0.,-1.));
#792=AXIS2_PLACEMENT_3D('',#789,#790,#791);
#793=PLANE('',#792);
#794=ORIENTED_EDGE('',*,*,#784,.F.);
#795=EDGE_LOOP('',(#794));
#796=FACE_BOUND('',#795,.T.);
#797=EDGE_CURVE('E624',#66,#461,#73,.T.);
#798=ORIENTED_EDGE('',*,*,#797,.T.);
#799=ORIENTED_EDGE('',*,*,#462,.T.);
#800=ORIENTED_EDGE('',*,*,#369,.T.);
#801=ORIENTED_EDGE('',*,*,#276,.T.);
#802=ORIENTED_EDGE('',*,*,#183,.T.);
#803=ORIENTED_EDGE('',*,*,#74,.T.);
#804=EDGE_LOOP('',(#798,#799,#800,#801,#802,#803));
#805=FACE_BOUND('',#804,.T.);
#806=ADVANCED_FACE('F671',(#796,#805),#793,.F.);
#807=DIRECTION('',(0.,1.,0.));
#808=VECTOR('',#807,1.);
#809=CARTESIAN_POINT('',(-3.82406529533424,91.9242942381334,4.62347538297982));
#810=LINE('',#809,#808);
#811=CARTESIAN_POINT('',(-3.82406529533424,5.92370889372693,4.62347538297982));
#812=VERTEX_POINT('',#811);
#813=EDGE_CURVE('E439',#812,#488,#810,.F.);
#814=ORIENTED_EDGE('',*,*,#813,.F.);
#815=EDGE_CURVE('E451',#812,#461,#468,.F.);
#816=ORIENTED_EDGE('',*,*,#815,.T.);
#817=ORIENTED_EDGE('',*,*,#797,.F.);
#818=CARTESIAN_POINT('',(-5.91607978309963,5.92370889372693,1.));
#819=VERTEX_POINT('',#818);
#820=EDGE_CURVE('E482',#66,#819,#64,.F.);
#821=ORIENTED_EDGE('',*,*,#820,.T.);
#822=DIRECTION('',(0.,1.,0.));
#823=VECTOR('',#822,1.);
#824=CARTESIAN_POINT('',(-5.91607978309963,91.9242942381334,1.));
#825=LINE('',#824,#823);
#826=EDGE_CURVE('E473',#819,#494,#825,.F.);
#827=ORIENTED_EDGE('',*,*,#826,.T.);
#828=ORIENTED_EDGE('',*,*,#495,.T.);
#829=EDGE_LOOP('',(#814,#816,#817,#821,#827,#828));
#830=FACE_BOUND('',#829,.T.);
#831=ADVANCED_FACE('F658',(#830),#23,.T.);
#832=ORIENTED_EDGE('',*,*,#50,.F.);
#833=DIRECTION('',(-0.50000000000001,0.,-0.866025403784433));
#834=VECTOR('',#833,1.);
#835=CARTESIAN_POINT('',(0.63397459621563,5.,3.09807621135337));
#836=LINE('',#835,#834);
#837=EDGE_CURVE('E337',#40,#90,#836,.T.);
#838=ORIENTED_EDGE('',*,*,#837,.T.);
#839=ORIENTED_EDGE('',*,*,#93,.T.);
#840=DIRECTION('',(-1.,0.,0.));
#841=VECTOR('',#840,1.);
#842=CARTESIAN_POINT('',(6.00000000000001,5.,-1.));
#843=LINE('',#842,#841);
#844=EDGE_CURVE('E463',#49,#92,#843,.T.);
#845=ORIENTED_EDGE('',*,*,#844,.F.);
#846=EDGE_LOOP('',(#832,#838,#839,#845));
#847=FACE_BOUND('',#846,.T.);
#848=ADVANCED_FACE('F670',(#847),#143,.F.);
#849=EDGE_CURVE('E611',#118,#511,#116,.T.);
#850=ORIENTED_EDGE('',*,*,#849,.T.);
#851=CARTESIAN_POINT('',(-9.35130677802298,15.973238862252,14.1969384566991));
#852=VERTEX_POINT('',#851);
#853=EDGE_CURVE('E450',#511,#852,#537,.T.);
#854=ORIENTED_EDGE('',*,*,#853,.T.);
#855=DIRECTION('',(0.,1.,0.));
#856=VECTOR('',#855,1.);
#857=CARTESIAN_POINT('',(-9.35130677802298,91.9242942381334,14.1969384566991));
#858=LINE('',#857,#856);
#859=EDGE_CURVE('E430',#490,#852,#858,.T.);
#860=ORIENTED_EDGE('',*,*,#859,.F.);
#861=ORIENTED_EDGE('',*,*,#505,.F.);
#862=DIRECTION('',(0.,1.,0.));
#863=VECTOR('',#862,1.);
#864=CARTESIAN_POINT('',(-16.9705627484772,91.9242942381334,1.));
#865=LINE('',#864,#863);
#866=CARTESIAN_POINT('',(-16.9705627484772,15.9732388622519,1.));
#867=VERTEX_POINT('',#866);
#868=EDGE_CURVE('E469',#502,#867,#865,.T.);
#869=ORIENTED_EDGE('',*,*,#868,.T.);
#870=EDGE_CURVE('E475',#867,#118,#125,.T.);
#871=ORIENTED_EDGE('',*,*,#870,.T.);
#872=EDGE_LOOP('',(#850,#854,#860,#861,#869,#871));
#873=FACE_BOUND('',#872,.T.);
#874=ADVANCED_FACE('F664',(#873),#83,.F.);
#875=CARTESIAN_POINT('',(17.,16.,0.));
#876=DIRECTION('',(0.,-1.,0.));
#877=DIRECTION('',(0.,0.,-1.));
#878=AXIS2_PLACEMENT_3D('',#875,#876,#877);
#879=PLANE('',#878);
#880=ORIENTED_EDGE('',*,*,#119,.F.);
#881=ORIENTED_EDGE('',*,*,#206,.F.);
#882=ORIENTED_EDGE('',*,*,#299,.F.);
#883=ORIENTED_EDGE('',*,*,#392,.F.);
#884=ORIENTED_EDGE('',*,*,#512,.F.);
#885=ORIENTED_EDGE('',*,*,#849,.F.);
#886=EDGE_LOOP('',(#880,#881,#882,#883,#884,#885));
#887=FACE_BOUND('',#886,.T.);
#888=CARTESIAN_POINT('',(0.,16.,0.));
#889=DIRECTION('',(0.,1.,0.));
#890=DIRECTION('',(0.,0.,1.));
#891=AXIS2_PLACEMENT_3D('',#888,#889,#890);
#892=CIRCLE('',#891,20.);
#893=CARTESIAN_POINT('',(0.,16.,20.));
#894=VERTEX_POINT('',#893);
#895=EDGE_CURVE('E607',#894,#894,#892,.T.);
#896=ORIENTED_EDGE('',*,*,#895,.T.);
#897=EDGE_LOOP('',(#896));
#898=FACE_BOUND('',#897,.T.);
#899=ADVANCED_FACE('F834',(#887,#898),#879,.F.);
#900=CARTESIAN_POINT('',(0.,91.9242942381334,0.));
#901=DIRECTION('',(0.,1.,0.));
#902=DIRECTION('',(0.,0.,1.));
#903=AXIS2_PLACEMENT_3D('',#900,#901,#902);
#904=CYLINDRICAL_SURFACE('',#903,20.);
#905=CARTESIAN_POINT('',(0.,5.,0.));
#906=DIRECTION('',(0.,1.,0.));
#907=DIRECTION('',(0.,0.,1.));
#908=AXIS2_PLACEMENT_3D('',#905,#906,#907);
#909=CIRCLE('',#908,20.);
#910=CARTESIAN_POINT('',(0.,5.,20.));
#911=VERTEX_POINT('',#910);
#912=EDGE_CURVE('E603',#911,#911,#909,.T.);
#913=ORIENTED_EDGE('',*,*,#912,.T.);
#914=EDGE_LOOP('',(#913));
#915=FACE_BOUND('',#914,.T.);
#916=ORIENTED_EDGE('',*,*,#895,.F.);
#917=EDGE_LOOP('',(#916));
#918=FACE_BOUND('',#917,.T.);
#919=ADVANCED_FACE('F898',(#915,#918),#904,.T.);
#920=CARTESIAN_POINT('',(20.,5.,0.));
#921=DIRECTION('',(0.,-1.,0.));
#922=DIRECTION('',(0.,0.,-1.));
#923=AXIS2_PLACEMENT_3D('',#920,#921,#922);
#924=PLANE('',#923);
#925=ORIENTED_EDGE('',*,*,#729,.T.);
#926=DIRECTION('',(-0.866025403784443,0.,-0.499999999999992));
#927=VECTOR('',#926,1.);
#928=CARTESIAN_POINT('',(-14.2705098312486,5.,-14.0125853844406));
#929=LINE('',#928,#927);
#930=CARTESIAN_POINT('',(-19.1506350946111,5.,-16.830127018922));
#931=VERTEX_POINT('',#930);
#932=EDGE_CURVE('E508',#724,#931,#929,.T.);
#933=ORIENTED_EDGE('',*,*,#932,.T.);
#934=CARTESIAN_POINT('',(-21.6506350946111,5.,-12.4999999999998));
#935=DIRECTION('',(0.,1.,0.));
#936=DIRECTION('',(-0.866025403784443,0.,-0.499999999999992));
#937=AXIS2_PLACEMENT_3D('',#934,#935,#936);
#938=CIRCLE('',#937,5.);
#939=CARTESIAN_POINT('',(-24.150635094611,5.,-8.16987298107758));
#940=VERTEX_POINT('',#939);
#941=EDGE_CURVE('E510',#931,#940,#938,.T.);
#942=ORIENTED_EDGE('',*,*,#941,.T.);
#943=DIRECTION('',(0.866025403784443,0.,0.499999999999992));
#944=VECTOR('',#943,1.);
#945=CARTESIAN_POINT('',(-24.150635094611,5.,-8.16987298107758));
#946=LINE('',#945,#944);
#947=EDGE_CURVE('E513',#940,#706,#946,.T.);
#948=ORIENTED_EDGE('',*,*,#947,.T.);
#949=ORIENTED_EDGE('',*,*,#707,.T.);
#950=DIRECTION('',(0.,0.,1.));
#951=VECTOR('',#950,1.);
#952=CARTESIAN_POINT('',(-5.,5.,19.3649167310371));
#953=LINE('',#952,#951);
#954=CARTESIAN_POINT('',(-4.99999999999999,5.,25.));
#955=VERTEX_POINT('',#954);
#956=EDGE_CURVE('E570',#697,#955,#953,.T.);
#957=ORIENTED_EDGE('',*,*,#956,.T.);
#958=CARTESIAN_POINT('',(0.,5.,25.));
#959=DIRECTION('',(0.,1.,0.));
#960=DIRECTION('',(0.,0.,1.));
#961=AXIS2_PLACEMENT_3D('',#958,#959,#960);
#962=CIRCLE('',#961,5.);
#963=CARTESIAN_POINT('',(5.,5.,25.));
#964=VERTEX_POINT('',#963);
#965=EDGE_CURVE('E572',#955,#964,#962,.T.);
#966=ORIENTED_EDGE('',*,*,#965,.T.);
#967=DIRECTION('',(0.,0.,-1.));
#968=VECTOR('',#967,1.);
#969=CARTESIAN_POINT('',(5.,5.,25.));
#970=LINE('',#969,#968);
#971=CARTESIAN_POINT('',(5.,5.,20.3960780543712));
#972=VERTEX_POINT('',#971);
#973=EDGE_CURVE('E575',#964,#972,#970,.T.);
#974=ORIENTED_EDGE('',*,*,#973,.T.);
#975=CARTESIAN_POINT('',(20.1635217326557,5.,-5.86791200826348));
#976=VERTEX_POINT('',#975);
#977=EDGE_CURVE('E601',#972,#976,#704,.T.);
#978=ORIENTED_EDGE('',*,*,#977,.T.);
#979=DIRECTION('',(0.866025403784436,0.,-0.500000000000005));
#980=VECTOR('',#979,1.);
#981=CARTESIAN_POINT('',(19.2705098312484,5.,-5.35233134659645));
#982=LINE('',#981,#980);
#983=CARTESIAN_POINT('',(24.1506350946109,5.,-8.16987298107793));
#984=VERTEX_POINT('',#983);
#985=EDGE_CURVE('E528',#976,#984,#982,.T.);
#986=ORIENTED_EDGE('',*,*,#985,.T.);
#987=CARTESIAN_POINT('',(21.6506350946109,5.,-12.5000000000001));
#988=DIRECTION('',(0.,1.,0.));
#989=DIRECTION('',(0.866025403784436,0.,-0.500000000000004));
#990=AXIS2_PLACEMENT_3D('',#987,#988,#989);
#991=CIRCLE('',#990,5.);
#992=CARTESIAN_POINT('',(19.1506350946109,5.,-16.8301270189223));
#993=VERTEX_POINT('',#992);
#994=EDGE_CURVE('E536',#984,#993,#991,.T.);
#995=ORIENTED_EDGE('',*,*,#994,.T.);
#996=DIRECTION('',(-0.866025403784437,0.,0.500000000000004));
#997=VECTOR('',#996,1.);
#998=CARTESIAN_POINT('',(19.1506350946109,5.,-16.8301270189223));
#999=LINE('',#998,#997);
#1000=EDGE_CURVE('E539',#993,#728,#999,.T.);
#1001=ORIENTED_EDGE('',*,*,#1000,.T.);
#1002=EDGE_LOOP('',(#925,#933,#942,#948,#949,#957,#966,#974,#978,#986,#995,#1001));
#1003=FACE_BOUND('',#1002,.T.);
#1004=CARTESIAN_POINT('',(-21.6506350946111,5.,-12.4999999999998));
#1005=DIRECTION('',(0.,-1.,0.));
#1006=DIRECTION('',(0.,0.,-1.));
#1007=AXIS2_PLACEMENT_3D('',#1004,#1005,#1006);
#1008=CIRCLE('',#1007,1.8);
#1009=CARTESIAN_POINT('',(-21.6506350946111,5.,-14.2999999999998));
#1010=VERTEX_POINT('',#1009);
#1011=EDGE_CURVE('E37',#1010,#1010,#1008,.T.);
#1012=ORIENTED_EDGE('',*,*,#1011,.T.);
#1013=EDGE_LOOP('',(#1012));
#1014=FACE_BOUND('',#1013,.T.);
#1015=CARTESIAN_POINT('',(21.6506350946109,5.,-12.5000000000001));
#1016=DIRECTION('',(0.,-1.,0.));
#1017=DIRECTION('',(0.,0.,-1.));
#1018=AXIS2_PLACEMENT_3D('',#1015,#1016,#1017);
#1019=CIRCLE('',#1018,1.8);
#1020=CARTESIAN_POINT('',(21.6506350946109,5.,-14.3000000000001));
#1021=VERTEX_POINT('',#1020);
#1022=EDGE_CURVE('E501',#1021,#1021,#1019,.T.);
#1023=ORIENTED_EDGE('',*,*,#1022,.T.);
#1024=EDGE_LOOP('',(#1023));
#1025=FACE_BOUND('',#1024,.T.);
#1026=ORIENTED_EDGE('',*,*,#912,.F.);
#1027=EDGE_LOOP('',(#1026));
#1028=FACE_BOUND('',#1027,.T.);
#1029=CARTESIAN_POINT('',(0.,5.,25.));
#1030=DIRECTION('',(0.,-1.,0.));
#1031=DIRECTION('',(0.,0.,-1.));
#1032=AXIS2_PLACEMENT_3D('',#1029,#1030,#1031);
#1033=CIRCLE('',#1032,1.8);
#1034=CARTESIAN_POINT('',(0.,5.,23.2));
#1035=VERTEX_POINT('',#1034);
#1036=EDGE_CURVE('E563',#1035,#1035,#1033,.T.);
#1037=ORIENTED_EDGE('',*,*,#1036,.T.);
#1038=EDGE_LOOP('',(#1037));
#1039=FACE_BOUND('',#1038,.T.);
#1040=ADVANCED_FACE('F634',(#1003,#1014,#1025,#1028,#1039),#924,.F.);
#1041=DIRECTION('',(0.,1.,0.));
#1042=VECTOR('',#1041,1.);
#1043=CARTESIAN_POINT('',(20.1635217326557,91.9242942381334,-5.86791200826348));
#1044=LINE('',#1043,#1042);
#1045=EDGE_CURVE('E548',#611,#976,#1044,.T.);
#1046=ORIENTED_EDGE('',*,*,#1045,.T.);
#1047=ORIENTED_EDGE('',*,*,#977,.F.);
#1048=DIRECTION('',(0.,1.,0.));
#1049=VECTOR('',#1048,1.);
#1050=CARTESIAN_POINT('',(5.,91.9242942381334,20.3960780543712));
#1051=LINE('',#1050,#1049);
#1052=EDGE_CURVE('E587',#972,#615,#1051,.F.);
#1053=ORIENTED_EDGE('',*,*,#1052,.T.);
#1054=ORIENTED_EDGE('',*,*,#616,.T.);
#1055=EDGE_LOOP('',(#1046,#1047,#1053,#1054));
#1056=FACE_BOUND('',#1055,.T.);
#1057=ADVANCED_FACE('F888',(#1056),#691,.T.);
#1058=CARTESIAN_POINT('',(0.,91.9242942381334,0.));
#1059=DIRECTION('',(0.,1.,0.));
#1060=DIRECTION('',(0.,0.,1.));
#1061=AXIS2_PLACEMENT_3D('',#1058,#1059,#1060);
#1062=CYLINDRICAL_SURFACE('',#1061,10.);
#1063=ORIENTED_EDGE('',*,*,#764,.T.);
#1064=EDGE_LOOP('',(#1063));
#1065=FACE_BOUND('',#1064,.T.);
#1066=ORIENTED_EDGE('',*,*,#555,.F.);
#1067=EDGE_LOOP('',(#1066));
#1068=FACE_BOUND('',#1067,.T.);
#1069=ADVANCED_FACE('F891',(#1065,#1068),#1062,.T.);
#1070=CARTESIAN_POINT('',(5.,-12.5981161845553,25.));
#1071=DIRECTION('',(1.,0.,0.));
#1072=DIRECTION('',(0.,0.,-1.));
#1073=AXIS2_PLACEMENT_3D('',#1070,#1071,#1072);
#1074=PLANE('',#1073);
#1075=ORIENTED_EDGE('',*,*,#1052,.F.);
#1076=ORIENTED_EDGE('',*,*,#973,.F.);
#1077=DIRECTION('',(0.,1.,0.));
#1078=VECTOR('',#1077,1.);
#1079=CARTESIAN_POINT('',(5.,-12.5981161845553,25.));
#1080=LINE('',#1079,#1078);
#1081=EDGE_CURVE('E567',#623,#964,#1080,.T.);
#1082=ORIENTED_EDGE('',*,*,#1081,.F.);
#1083=ORIENTED_EDGE('',*,*,#624,.F.);
#1084=EDGE_LOOP('',(#1075,#1076,#1082,#1083));
#1085=FACE_BOUND('',#1084,.T.);
#1086=ADVANCED_FACE('F931',(#1085),#1074,.T.);
#1087=CARTESIAN_POINT('',(-5.,-12.5981161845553,19.3649167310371));
#1088=DIRECTION('',(-1.,0.,0.));
#1089=DIRECTION('',(0.,0.,1.));
#1090=AXIS2_PLACEMENT_3D('',#1087,#1088,#1089);
#1091=PLANE('',#1090);
#1092=ORIENTED_EDGE('',*,*,#698,.F.);
#1093=ORIENTED_EDGE('',*,*,#641,.F.);
#1094=DIRECTION('',(0.,1.,0.));
#1095=VECTOR('',#1094,1.);
#1096=CARTESIAN_POINT('',(-4.99999999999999,-12.5981161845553,25.));
#1097=LINE('',#1096,#1095);
#1098=EDGE_CURVE('E578',#632,#955,#1097,.T.);
#1099=ORIENTED_EDGE('',*,*,#1098,.T.);
#1100=ORIENTED_EDGE('',*,*,#956,.F.);
#1101=EDGE_LOOP('',(#1092,#1093,#1099,#1100));
#1102=FACE_BOUND('',#1101,.T.);
#1103=ADVANCED_FACE('F939',(#1102),#1091,.T.);
#1104=CARTESIAN_POINT('',(0.,-12.5981161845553,25.));
#1105=DIRECTION('',(0.,1.,0.));
#1106=DIRECTION('',(0.,0.,1.));
#1107=AXIS2_PLACEMENT_3D('',#1104,#1105,#1106);
#1108=CYLINDRICAL_SURFACE('',#1107,5.);
#1109=ORIENTED_EDGE('',*,*,#633,.F.);
#1110=ORIENTED_EDGE('',*,*,#1081,.T.);
#1111=ORIENTED_EDGE('',*,*,#965,.F.);
#1112=ORIENTED_EDGE('',*,*,#1098,.F.);
#1113=EDGE_LOOP('',(#1109,#1110,#1111,#1112));
#1114=FACE_BOUND('',#1113,.T.);
#1115=ADVANCED_FACE('F947',(#1114),#1108,.T.);
#1116=CARTESIAN_POINT('',(0.,2.,25.));
#1117=DIRECTION('',(0.,-1.,0.));
#1118=DIRECTION('',(0.,0.,-1.));
#1119=AXIS2_PLACEMENT_3D('',#1116,#1117,#1118);
#1120=CYLINDRICAL_SURFACE('',#1119,1.8);
#1121=CARTESIAN_POINT('',(0.,3.65,25.));
#1122=DIRECTION('',(0.,-1.,0.));
#1123=DIRECTION('',(0.,0.,-1.));
#1124=AXIS2_PLACEMENT_3D('',#1121,#1122,#1123);
#1125=CIRCLE('',#1124,1.8);
#1126=CARTESIAN_POINT('',(0.,3.65,23.2));
#1127=VERTEX_POINT('',#1126);
#1128=EDGE_CURVE('E560',#1127,#1127,#1125,.T.);
#1129=ORIENTED_EDGE('',*,*,#1128,.T.);
#1130=EDGE_LOOP('',(#1129));
#1131=FACE_BOUND('',#1130,.T.);
#1132=ORIENTED_EDGE('',*,*,#1036,.F.);
#1133=EDGE_LOOP('',(#1132));
#1134=FACE_BOUND('',#1133,.T.);
#1135=ADVANCED_FACE('F954',(#1131,#1134),#1120,.F.);
#1136=CARTESIAN_POINT('',(1.80000000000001,3.65,25.));
#1137=DIRECTION('',(0.,1.,0.));
#1138=DIRECTION('',(0.,0.,1.));
#1139=AXIS2_PLACEMENT_3D('',#1136,#1137,#1138);
#1140=PLANE('',#1139);
#1141=ORIENTED_EDGE('',*,*,#1128,.F.);
#1142=EDGE_LOOP('',(#1141));
#1143=FACE_BOUND('',#1142,.T.);
#1144=CARTESIAN_POINT('',(0.,3.65,25.));
#1145=DIRECTION('',(0.,-1.,0.));
#1146=DIRECTION('',(0.,0.,-1.));
#1147=AXIS2_PLACEMENT_3D('',#1144,#1145,#1146);
#1148=CIRCLE('',#1147,3.35);
#1149=CARTESIAN_POINT('',(0.,3.65,21.65));
#1150=VERTEX_POINT('',#1149);
#1151=EDGE_CURVE('E557',#1150,#1150,#1148,.T.);
#1152=ORIENTED_EDGE('',*,*,#1151,.T.);
#1153=EDGE_LOOP('',(#1152));
#1154=FACE_BOUND('',#1153,.T.);
#1155=ADVANCED_FACE('F962',(#1143,#1154),#1140,.F.);
#1156=CARTESIAN_POINT('',(0.,2.,25.));
#1157=DIRECTION('',(0.,-1.,0.));
#1158=DIRECTION('',(0.,0.,-1.));
#1159=AXIS2_PLACEMENT_3D('',#1156,#1157,#1158);
#1160=CYLINDRICAL_SURFACE('',#1159,3.35);
#1161=ORIENTED_EDGE('',*,*,#1151,.F.);
#1162=EDGE_LOOP('',(#1161));
#1163=FACE_BOUND('',#1162,.T.);
#1164=ORIENTED_EDGE('',*,*,#566,.T.);
#1165=EDGE_LOOP('',(#1164));
#1166=FACE_BOUND('',#1165,.T.);
#1167=ADVANCED_FACE('F970',(#1163,#1166),#1160,.F.);
#1168=CARTESIAN_POINT('',(19.1506350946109,-15.3445482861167,-16.8301270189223));
#1169=DIRECTION('',(-0.500000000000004,0.,-0.866025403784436));
#1170=DIRECTION('',(-0.866025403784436,0.,0.500000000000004));
#1171=AXIS2_PLACEMENT_3D('',#1168,#1169,#1170);
#1172=PLANE('',#1171);
#1173=ORIENTED_EDGE('',*,*,#735,.F.);
#1174=ORIENTED_EDGE('',*,*,#1000,.F.);
#1175=DIRECTION('',(0.,1.,0.));
#1176=VECTOR('',#1175,1.);
#1177=CARTESIAN_POINT('',(19.1506350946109,-15.3445482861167,-16.8301270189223));
#1178=LINE('',#1177,#1176);
#1179=EDGE_CURVE('E532',#594,#993,#1178,.T.);
#1180=ORIENTED_EDGE('',*,*,#1179,.F.);
#1181=ORIENTED_EDGE('',*,*,#595,.F.);
#1182=EDGE_LOOP('',(#1173,#1174,#1180,#1181));
#1183=FACE_BOUND('',#1182,.T.);
#1184=ADVANCED_FACE('F978',(#1183),#1172,.T.);
#1185=CARTESIAN_POINT('',(19.2705098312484,-15.3445482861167,-5.35233134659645));
#1186=DIRECTION('',(0.500000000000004,0.,0.866025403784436));
#1187=DIRECTION('',(0.866025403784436,0.,-0.500000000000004));
#1188=AXIS2_PLACEMENT_3D('',#1185,#1186,#1187);
#1189=PLANE('',#1188);
#1190=ORIENTED_EDGE('',*,*,#1045,.F.);
#1191=ORIENTED_EDGE('',*,*,#612,.F.);
#1192=DIRECTION('',(0.,1.,0.));
#1193=VECTOR('',#1192,1.);
#1194=CARTESIAN_POINT('',(24.1506350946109,-15.3445482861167,-8.16987298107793));
#1195=LINE('',#1194,#1193);
#1196=EDGE_CURVE('E542',#603,#984,#1195,.T.);
#1197=ORIENTED_EDGE('',*,*,#1196,.T.);
#1198=ORIENTED_EDGE('',*,*,#985,.F.);
#1199=EDGE_LOOP('',(#1190,#1191,#1197,#1198));
#1200=FACE_BOUND('',#1199,.T.);
#1201=ADVANCED_FACE('F986',(#1200),#1189,.T.);
#1202=CARTESIAN_POINT('',(21.6506350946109,-15.3445482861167,-12.5000000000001));
#1203=DIRECTION('',(0.,1.,0.));
#1204=DIRECTION('',(0.,0.,1.));
#1205=AXIS2_PLACEMENT_3D('',#1202,#1203,#1204);
#1206=CYLINDRICAL_SURFACE('',#1205,5.);
#1207=ORIENTED_EDGE('',*,*,#604,.F.);
#1208=ORIENTED_EDGE('',*,*,#1179,.T.);
#1209=ORIENTED_EDGE('',*,*,#994,.F.);
#1210=ORIENTED_EDGE('',*,*,#1196,.F.);
#1211=EDGE_LOOP('',(#1207,#1208,#1209,#1210));
#1212=FACE_BOUND('',#1211,.T.);
#1213=ADVANCED_FACE('F994',(#1212),#1206,.T.);
#1214=CARTESIAN_POINT('',(-24.150635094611,-15.3445482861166,-8.16987298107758));
#1215=DIRECTION('',(-0.499999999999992,0.,0.866025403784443));
#1216=DIRECTION('',(0.866025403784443,0.,0.499999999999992));
#1217=AXIS2_PLACEMENT_3D('',#1214,#1215,#1216);
#1218=PLANE('',#1217);
#1219=ORIENTED_EDGE('',*,*,#713,.F.);
#1220=ORIENTED_EDGE('',*,*,#947,.F.);
#1221=DIRECTION('',(0.,1.,0.));
#1222=VECTOR('',#1221,1.);
#1223=CARTESIAN_POINT('',(-24.150635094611,-15.3445482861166,-8.16987298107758));
#1224=LINE('',#1223,#1222);
#1225=EDGE_CURVE('E505',#652,#940,#1224,.T.);
#1226=ORIENTED_EDGE('',*,*,#1225,.F.);
#1227=ORIENTED_EDGE('',*,*,#653,.F.);
#1228=EDGE_LOOP('',(#1219,#1220,#1226,#1227));
#1229=FACE_BOUND('',#1228,.T.);
#1230=ADVANCED_FACE('F1002',(#1229),#1218,.T.);
#1231=CARTESIAN_POINT('',(-14.2705098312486,-15.3445482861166,-14.0125853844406));
#1232=DIRECTION('',(0.499999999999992,0.,-0.866025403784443));
#1233=DIRECTION('',(-0.866025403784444,0.,-0.499999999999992));
#1234=AXIS2_PLACEMENT_3D('',#1231,#1232,#1233);
#1235=PLANE('',#1234);
#1236=ORIENTED_EDGE('',*,*,#725,.F.);
#1237=ORIENTED_EDGE('',*,*,#578,.F.);
#1238=DIRECTION('',(0.,1.,0.));
#1239=VECTOR('',#1238,1.);
#1240=CARTESIAN_POINT('',(-19.1506350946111,-15.3445482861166,-16.830127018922));
#1241=LINE('',#1240,#1239);
#1242=EDGE_CURVE('E516',#575,#931,#1241,.T.);
#1243=ORIENTED_EDGE('',*,*,#1242,.T.);
#1244=ORIENTED_EDGE('',*,*,#932,.F.);
#1245=EDGE_LOOP('',(#1236,#1237,#1243,#1244));
#1246=FACE_BOUND('',#1245,.T.);
#1247=ADVANCED_FACE('F650',(#1246),#1235,.T.);
#1248=CARTESIAN_POINT('',(-21.6506350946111,-15.3445482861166,-12.4999999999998));
#1249=DIRECTION('',(0.,1.,0.));
#1250=DIRECTION('',(0.,0.,1.));
#1251=AXIS2_PLACEMENT_3D('',#1248,#1249,#1250);
#1252=CYLINDRICAL_SURFACE('',#1251,5.);
#1253=ORIENTED_EDGE('',*,*,#660,.F.);
#1254=ORIENTED_EDGE('',*,*,#1225,.T.);
#1255=ORIENTED_EDGE('',*,*,#941,.F.);
#1256=ORIENTED_EDGE('',*,*,#1242,.F.);
#1257=EDGE_LOOP('',(#1253,#1254,#1255,#1256));
#1258=FACE_BOUND('',#1257,.T.);
#1259=ADVANCED_FACE('F640',(#1258),#1252,.T.);
#1260=CARTESIAN_POINT('',(21.6506350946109,2.,-12.5000000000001));
#1261=DIRECTION('',(0.,-1.,0.));
#1262=DIRECTION('',(0.,0.,-1.));
#1263=AXIS2_PLACEMENT_3D('',#1260,#1261,#1262);
#1264=CYLINDRICAL_SURFACE('',#1263,1.8);
#1265=CARTESIAN_POINT('',(21.6506350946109,3.65,-12.5000000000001));
#1266=DIRECTION('',(0.,-1.,0.));
#1267=DIRECTION('',(0.,0.,-1.));
#1268=AXIS2_PLACEMENT_3D('',#1265,#1266,#1267);
#1269=CIRCLE('',#1268,1.8);
#1270=CARTESIAN_POINT('',(21.6506350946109,3.65,-14.3000000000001));
#1271=VERTEX_POINT('',#1270);
#1272=EDGE_CURVE('E498',#1271,#1271,#1269,.T.);
#1273=ORIENTED_EDGE('',*,*,#1272,.T.);
#1274=EDGE_LOOP('',(#1273));
#1275=FACE_BOUND('',#1274,.T.);
#1276=ORIENTED_EDGE('',*,*,#1022,.F.);
#1277=EDGE_LOOP('',(#1276));
#1278=FACE_BOUND('',#1277,.T.);
#1279=ADVANCED_FACE('F637',(#1275,#1278),#1264,.F.);
#1280=CARTESIAN_POINT('',(23.4506350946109,3.65,-12.5000000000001));
#1281=DIRECTION('',(0.,1.,0.));
#1282=DIRECTION('',(0.,0.,1.));
#1283=AXIS2_PLACEMENT_3D('',#1280,#1281,#1282);
#1284=PLANE('',#1283);
#1285=ORIENTED_EDGE('',*,*,#1272,.F.);
#1286=EDGE_LOOP('',(#1285));
#1287=FACE_BOUND('',#1286,.T.);
#1288=CARTESIAN_POINT('',(21.6506350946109,3.65,-12.5000000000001));
#1289=DIRECTION('',(0.,-1.,0.));
#1290=DIRECTION('',(0.,0.,-1.));
#1291=AXIS2_PLACEMENT_3D('',#1288,#1289,#1290);
#1292=CIRCLE('',#1291,3.35);
#1293=CARTESIAN_POINT('',(21.6506350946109,3.65,-15.8500000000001));
#1294=VERTEX_POINT('',#1293);
#1295=EDGE_CURVE('E495',#1294,#1294,#1292,.T.);
#1296=ORIENTED_EDGE('',*,*,#1295,.T.);
#1297=EDGE_LOOP('',(#1296));
#1298=FACE_BOUND('',#1297,.T.);
#1299=ADVANCED_FACE('F639',(#1287,#1298),#1284,.F.);
#1300=CARTESIAN_POINT('',(21.6506350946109,2.,-12.5000000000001));
#1301=DIRECTION('',(0.,-1.,0.));
#1302=DIRECTION('',(0.,0.,-1.));
#1303=AXIS2_PLACEMENT_3D('',#1300,#1301,#1302);
#1304=CYLINDRICAL_SURFACE('',#1303,3.35);
#1305=ORIENTED_EDGE('',*,*,#1295,.F.);
#1306=EDGE_LOOP('',(#1305));
#1307=FACE_BOUND('',#1306,.T.);
#1308=ORIENTED_EDGE('',*,*,#671,.T.);
#1309=EDGE_LOOP('',(#1308));
#1310=FACE_BOUND('',#1309,.T.);
#1311=ADVANCED_FACE('F647',(#1307,#1310),#1304,.F.);
#1312=CARTESIAN_POINT('',(-21.6506350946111,2.,-12.4999999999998));
#1313=DIRECTION('',(0.,-1.,0.));
#1314=DIRECTION('',(0.,0.,-1.));
#1315=AXIS2_PLACEMENT_3D('',#1312,#1313,#1314);
#1316=CYLINDRICAL_SURFACE('',#1315,1.8);
#1317=CARTESIAN_POINT('',(-21.6506350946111,3.65,-12.4999999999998));
#1318=DIRECTION('',(0.,-1.,0.));
#1319=DIRECTION('',(0.,0.,-1.));
#1320=AXIS2_PLACEMENT_3D('',#1317,#1318,#1319);
#1321=CIRCLE('',#1320,1.8);
#1322=CARTESIAN_POINT('',(-21.6506350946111,3.65,-14.2999999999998));
#1323=VERTEX_POINT('',#1322);
#1324=EDGE_CURVE('E489',#1323,#1323,#1321,.T.);
#1325=ORIENTED_EDGE('',*,*,#1324,.T.);
#1326=EDGE_LOOP('',(#1325));
#1327=FACE_BOUND('',#1326,.T.);
#1328=ORIENTED_EDGE('',*,*,#1011,.F.);
#1329=EDGE_LOOP('',(#1328));
#1330=FACE_BOUND('',#1329,.T.);
#1331=ADVANCED_FACE('F860',(#1327,#1330),#1316,.F.);
#1332=CARTESIAN_POINT('',(-19.8506350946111,3.65,-12.4999999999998));
#1333=DIRECTION('',(0.,1.,0.));
#1334=DIRECTION('',(0.,0.,1.));
#1335=AXIS2_PLACEMENT_3D('',#1332,#1333,#1334);
#1336=PLANE('',#1335);
#1337=ORIENTED_EDGE('',*,*,#1324,.F.);
#1338=EDGE_LOOP('',(#1337));
#1339=FACE_BOUND('',#1338,.T.);
#1340=CARTESIAN_POINT('',(-21.6506350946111,3.65,-12.4999999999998));
#1341=DIRECTION('',(0.,-1.,0.));
#1342=DIRECTION('',(0.,0.,-1.));
#1343=AXIS2_PLACEMENT_3D('',#1340,#1341,#1342);
#1344=CIRCLE('',#1343,3.35);
#1345=CARTESIAN_POINT('',(-21.6506350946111,3.65,-15.8499999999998));
#1346=VERTEX_POINT('',#1345);
#1347=EDGE_CURVE('E486',#1346,#1346,#1344,.T.);
#1348=ORIENTED_EDGE('',*,*,#1347,.T.);
#1349=EDGE_LOOP('',(#1348));
#1350=FACE_BOUND('',#1349,.T.);
#1351=ADVANCED_FACE('F856',(#1339,#1350),#1336,.F.);
#1352=CARTESIAN_POINT('',(-21.6506350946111,2.,-12.4999999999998));
#1353=DIRECTION('',(0.,-1.,0.));
#1354=DIRECTION('',(0.,0.,-1.));
#1355=AXIS2_PLACEMENT_3D('',#1352,#1353,#1354);
#1356=CYLINDRICAL_SURFACE('',#1355,3.35);
#1357=ORIENTED_EDGE('',*,*,#1347,.F.);
#1358=EDGE_LOOP('',(#1357));
#1359=FACE_BOUND('',#1358,.T.);
#1360=ORIENTED_EDGE('',*,*,#682,.T.);
#1361=EDGE_LOOP('',(#1360));
#1362=FACE_BOUND('',#1361,.T.);
#1363=ADVANCED_FACE('F849',(#1359,#1362),#1356,.F.);
#1364=CARTESIAN_POINT('',(-17.,16.,0.));
#1365=DIRECTION('',(-0.672672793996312,-0.739940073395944,0.));
#1366=DIRECTION('',(0.739940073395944,-0.672672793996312,0.));
#1367=AXIS2_PLACEMENT_3D('',#1364,#1365,#1366);
#1368=PLANE('',#1367);
#1369=ORIENTED_EDGE('',*,*,#820,.F.);
#1370=ORIENTED_EDGE('',*,*,#67,.F.);
#1371=DIRECTION('',(0.739940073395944,-0.672672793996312,0.));
#1372=VECTOR('',#1371,1.);
#1373=CARTESIAN_POINT('',(-17.,16.,-1.));
#1374=LINE('',#1373,#1372);
#1375=EDGE_CURVE('E458',#127,#57,#1374,.T.);
#1376=ORIENTED_EDGE('',*,*,#1375,.F.);
#1377=ORIENTED_EDGE('',*,*,#128,.F.);
#1378=ORIENTED_EDGE('',*,*,#870,.F.);
#1379=DIRECTION('',(0.739940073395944,-0.672672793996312,0.));
#1380=VECTOR('',#1379,1.);
#1381=CARTESIAN_POINT('',(-17.,16.,1.));
#1382=LINE('',#1381,#1380);
#1383=EDGE_CURVE('E454',#867,#819,#1382,.T.);
#1384=ORIENTED_EDGE('',*,*,#1383,.T.);
#1385=EDGE_LOOP('',(#1369,#1370,#1376,#1377,#1378,#1384));
#1386=FACE_BOUND('',#1385,.T.);
#1387=ADVANCED_FACE('F752',(#1386),#1368,.F.);
#1388=CARTESIAN_POINT('',(0.,8.,1.));
#1389=DIRECTION('',(0.,0.,1.));
#1390=DIRECTION('',(1.,0.,0.));
#1391=AXIS2_PLACEMENT_3D('',#1388,#1389,#1390);
#1392=PLANE('',#1391);
#1393=ORIENTED_EDGE('',*,*,#826,.F.);
#1394=ORIENTED_EDGE('',*,*,#1383,.F.);
#1395=ORIENTED_EDGE('',*,*,#868,.F.);
#1396=ORIENTED_EDGE('',*,*,#503,.F.);
#1397=EDGE_LOOP('',(#1393,#1394,#1395,#1396));
#1398=FACE_BOUND('',#1397,.T.);
#1399=ADVANCED_FACE('F841',(#1398),#1392,.T.);
#1400=CARTESIAN_POINT('',(0.,8.,-1.));
#1401=DIRECTION('',(0.,0.,1.));
#1402=DIRECTION('',(1.,0.,0.));
#1403=AXIS2_PLACEMENT_3D('',#1400,#1401,#1402);
#1404=PLANE('',#1403);
#1405=ORIENTED_EDGE('',*,*,#1375,.T.);
#1406=ORIENTED_EDGE('',*,*,#58,.T.);
#1407=ORIENTED_EDGE('',*,*,#844,.T.);
#1408=ORIENTED_EDGE('',*,*,#134,.T.);
#1409=EDGE_LOOP('',(#1405,#1406,#1407,#1408));
#1410=FACE_BOUND('',#1409,.T.);
#1411=ADVANCED_FACE('F747',(#1410),#1404,.F.);
#1412=CARTESIAN_POINT('',(-8.49999999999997,16.,14.7224318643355));
#1413=DIRECTION('',(-0.336336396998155,-0.739940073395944,0.582551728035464));
#1414=DIRECTION('',(0.36997003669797,-0.672672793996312,-0.64080690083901));
#1415=AXIS2_PLACEMENT_3D('',#1412,#1413,#1414);
#1416=PLANE('',#1415);
#1417=ORIENTED_EDGE('',*,*,#471,.F.);
#1418=ORIENTED_EDGE('',*,*,#815,.F.);
#1419=DIRECTION('',(0.36997003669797,-0.672672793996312,-0.64080690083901));
#1420=VECTOR('',#1419,1.);
#1421=CARTESIAN_POINT('',(-9.36602540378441,16.,14.2224318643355));
#1422=LINE('',#1421,#1420);
#1423=EDGE_CURVE('E431',#852,#812,#1422,.T.);
#1424=ORIENTED_EDGE('',*,*,#1423,.F.);
#1425=ORIENTED_EDGE('',*,*,#853,.F.);
#1426=ORIENTED_EDGE('',*,*,#538,.F.);
#1427=DIRECTION('',(0.36997003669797,-0.672672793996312,-0.64080690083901));
#1428=VECTOR('',#1427,1.);
#1429=CARTESIAN_POINT('',(-7.63397459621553,16.,15.2224318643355));
#1430=LINE('',#1429,#1428);
#1431=EDGE_CURVE('E427',#530,#470,#1430,.T.);
#1432=ORIENTED_EDGE('',*,*,#1431,.T.);
#1433=EDGE_LOOP('',(#1417,#1418,#1424,#1425,#1426,#1432));
#1434=FACE_BOUND('',#1433,.T.);
#1435=ADVANCED_FACE('F765',(#1434),#1416,.F.);
#1436=CARTESIAN_POINT('',(-1.08253175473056,8.,3.87500000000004));
#1437=DIRECTION('',(0.86602540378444,0.,0.499999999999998));
#1438=DIRECTION('',(0.499999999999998,0.,-0.86602540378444));
#1439=AXIS2_PLACEMENT_3D('',#1436,#1437,#1438);
#1440=PLANE('',#1439);
#1441=ORIENTED_EDGE('',*,*,#477,.F.);
#1442=ORIENTED_EDGE('',*,*,#1431,.F.);
#1443=ORIENTED_EDGE('',*,*,#531,.F.);
#1444=ORIENTED_EDGE('',*,*,#443,.F.);
#1445=EDGE_LOOP('',(#1441,#1442,#1443,#1444));
#1446=FACE_BOUND('',#1445,.T.);
#1447=ADVANCED_FACE('F774',(#1446),#1440,.T.);
#1448=CARTESIAN_POINT('',(-2.81458256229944,8.,2.87500000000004));
#1449=DIRECTION('',(0.86602540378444,0.,0.499999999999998));
#1450=DIRECTION('',(0.499999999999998,0.,-0.86602540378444));
#1451=AXIS2_PLACEMENT_3D('',#1448,#1449,#1450);
#1452=PLANE('',#1451);
#1453=ORIENTED_EDGE('',*,*,#1423,.T.);
#1454=ORIENTED_EDGE('',*,*,#813,.T.);
#1455=ORIENTED_EDGE('',*,*,#491,.T.);
#1456=ORIENTED_EDGE('',*,*,#859,.T.);
#1457=EDGE_LOOP('',(#1453,#1454,#1455,#1456));
#1458=FACE_BOUND('',#1457,.T.);
#1459=ADVANCED_FACE('F837',(#1458),#1452,.F.);
#1460=CARTESIAN_POINT('',(8.50000000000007,16.,14.7224318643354));
#1461=DIRECTION('',(0.336336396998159,-0.739940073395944,0.582551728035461));
#1462=DIRECTION('',(-0.369970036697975,-0.672672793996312,-0.640806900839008));
#1463=AXIS2_PLACEMENT_3D('',#1460,#1461,#1462);
#1464=PLANE('',#1463);
#1465=ORIENTED_EDGE('',*,*,#378,.F.);
#1466=ORIENTED_EDGE('',*,*,#458,.F.);
#1467=DIRECTION('',(-0.369970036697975,-0.672672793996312,-0.640806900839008));
#1468=VECTOR('',#1467,1.);
#1469=CARTESIAN_POINT('',(7.63397459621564,16.,15.2224318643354));
#1470=LINE('',#1469,#1468);
#1471=EDGE_CURVE('E404',#515,#455,#1470,.T.);
#1472=ORIENTED_EDGE('',*,*,#1471,.F.);
#1473=ORIENTED_EDGE('',*,*,#516,.F.);
#1474=ORIENTED_EDGE('',*,*,#418,.F.);
#1475=DIRECTION('',(-0.369970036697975,-0.672672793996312,-0.640806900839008));
#1476=VECTOR('',#1475,1.);
#1477=CARTESIAN_POINT('',(9.36602540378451,16.,14.2224318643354));
#1478=LINE('',#1477,#1476);
#1479=EDGE_CURVE('E400',#410,#377,#1478,.T.);
#1480=ORIENTED_EDGE('',*,*,#1479,.T.);
#1481=EDGE_LOOP('',(#1465,#1466,#1472,#1473,#1474,#1480));
#1482=FACE_BOUND('',#1481,.T.);
#1483=ADVANCED_FACE('F810',(#1482),#1464,.F.);
#1484=CARTESIAN_POINT('',(2.81458256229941,8.,2.87499999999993));
#1485=DIRECTION('',(0.866025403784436,0.,-0.500000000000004));
#1486=DIRECTION('',(-0.500000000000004,0.,-0.866025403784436));
#1487=AXIS2_PLACEMENT_3D('',#1484,#1485,#1486);
#1488=PLANE('',#1487);
#1489=ORIENTED_EDGE('',*,*,#384,.F.);
#1490=ORIENTED_EDGE('',*,*,#1479,.F.);
#1491=ORIENTED_EDGE('',*,*,#411,.F.);
#1492=ORIENTED_EDGE('',*,*,#350,.F.);
#1493=EDGE_LOOP('',(#1489,#1490,#1491,#1492));
#1494=FACE_BOUND('',#1493,.T.);
#1495=ADVANCED_FACE('F1317',(#1494),#1488,.T.);
#1496=CARTESIAN_POINT('',(1.08253175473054,8.,3.87499999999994));
#1497=DIRECTION('',(0.866025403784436,0.,-0.500000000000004));
#1498=DIRECTION('',(-0.500000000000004,0.,-0.866025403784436));
#1499=AXIS2_PLACEMENT_3D('',#1496,#1497,#1498);
#1500=PLANE('',#1499);
#1501=ORIENTED_EDGE('',*,*,#1471,.T.);
#1502=ORIENTED_EDGE('',*,*,#456,.T.);
#1503=ORIENTED_EDGE('',*,*,#431,.T.);
#1504=ORIENTED_EDGE('',*,*,#522,.T.);
#1505=EDGE_LOOP('',(#1501,#1502,#1503,#1504));
#1506=FACE_BOUND('',#1505,.T.);
#1507=ADVANCED_FACE('F806',(#1506),#1500,.F.);
#1508=CARTESIAN_POINT('',(17.,16.,0.));
#1509=DIRECTION('',(0.672672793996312,-0.739940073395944,0.));
#1510=DIRECTION('',(-0.739940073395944,-0.672672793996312,0.));
#1511=AXIS2_PLACEMENT_3D('',#1508,#1509,#1510);
#1512=PLANE('',#1511);
#1513=ORIENTED_EDGE('',*,*,#285,.F.);
#1514=ORIENTED_EDGE('',*,*,#365,.F.);
#1515=DIRECTION('',(-0.739940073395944,-0.672672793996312,0.));
#1516=VECTOR('',#1515,1.);
#1517=CARTESIAN_POINT('',(17.,16.,1.));
#1518=LINE('',#1517,#1516);
#1519=EDGE_CURVE('E377',#395,#362,#1518,.T.);
#1520=ORIENTED_EDGE('',*,*,#1519,.F.);
#1521=ORIENTED_EDGE('',*,*,#396,.F.);
#1522=ORIENTED_EDGE('',*,*,#325,.F.);
#1523=DIRECTION('',(-0.739940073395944,-0.672672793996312,0.));
#1524=VECTOR('',#1523,1.);
#1525=CARTESIAN_POINT('',(17.,16.,-1.));
#1526=LINE('',#1525,#1524);
#1527=EDGE_CURVE('E373',#317,#284,#1526,.T.);
#1528=ORIENTED_EDGE('',*,*,#1527,.T.);
#1529=EDGE_LOOP('',(#1513,#1514,#1520,#1521,#1522,#1528));
#1530=FACE_BOUND('',#1529,.T.);
#1531=ADVANCED_FACE('F792',(#1530),#1512,.F.);
#1532=CARTESIAN_POINT('',(0.,8.00000000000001,-1.));
#1533=DIRECTION('',(0.,0.,-1.));
#1534=DIRECTION('',(-1.,0.,0.));
#1535=AXIS2_PLACEMENT_3D('',#1532,#1533,#1534);
#1536=PLANE('',#1535);
#1537=ORIENTED_EDGE('',*,*,#291,.F.);
#1538=ORIENTED_EDGE('',*,*,#1527,.F.);
#1539=ORIENTED_EDGE('',*,*,#318,.F.);
#1540=ORIENTED_EDGE('',*,*,#257,.F.);
#1541=EDGE_LOOP('',(#1537,#1538,#1539,#1540));
#1542=FACE_BOUND('',#1541,.T.);
#1543=ADVANCED_FACE('F786',(#1542),#1536,.T.);
#1544=CARTESIAN_POINT('',(0.,8.00000000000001,1.));
#1545=DIRECTION('',(0.,0.,-1.));
#1546=DIRECTION('',(-1.,0.,0.));
#1547=AXIS2_PLACEMENT_3D('',#1544,#1545,#1546);
#1548=PLANE('',#1547);
#1549=ORIENTED_EDGE('',*,*,#1519,.T.);
#1550=ORIENTED_EDGE('',*,*,#363,.T.);
#1551=ORIENTED_EDGE('',*,*,#338,.T.);
#1552=ORIENTED_EDGE('',*,*,#402,.T.);
#1553=EDGE_LOOP('',(#1549,#1550,#1551,#1552));
#1554=FACE_BOUND('',#1553,.T.);
#1555=ADVANCED_FACE('F799',(#1554),#1548,.F.);
#1556=CARTESIAN_POINT('',(8.49999999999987,16.,-14.7224318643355));
#1557=DIRECTION('',(0.336336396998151,-0.739940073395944,-0.582551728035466));
#1558=DIRECTION('',(-0.369970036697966,-0.672672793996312,0.640806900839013));
#1559=AXIS2_PLACEMENT_3D('',#1556,#1557,#1558);
#1560=PLANE('',#1559);
#1561=ORIENTED_EDGE('',*,*,#192,.F.);
#1562=ORIENTED_EDGE('',*,*,#272,.F.);
#1563=DIRECTION('',(-0.369970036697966,-0.672672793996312,0.640806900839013));
#1564=VECTOR('',#1563,1.);
#1565=CARTESIAN_POINT('',(9.36602540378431,16.,-14.2224318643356));
#1566=LINE('',#1565,#1564);
#1567=EDGE_CURVE('E351',#302,#269,#1566,.T.);
#1568=ORIENTED_EDGE('',*,*,#1567,.F.);
#1569=ORIENTED_EDGE('',*,*,#303,.F.);
#1570=ORIENTED_EDGE('',*,*,#232,.F.);
#1571=DIRECTION('',(-0.369970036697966,-0.672672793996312,0.640806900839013));
#1572=VECTOR('',#1571,1.);
#1573=CARTESIAN_POINT('',(7.63397459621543,16.,-15.2224318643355));
#1574=LINE('',#1573,#1572);
#1575=EDGE_CURVE('E347',#224,#191,#1574,.T.);
#1576=ORIENTED_EDGE('',*,*,#1575,.T.);
#1577=EDGE_LOOP('',(#1561,#1562,#1568,#1569,#1570,#1576));
#1578=FACE_BOUND('',#1577,.T.);
#1579=ADVANCED_FACE('F723',(#1578),#1560,.F.);
#1580=CARTESIAN_POINT('',(-2.81458256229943,8.00000000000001,2.87500000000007));
#1581=DIRECTION('',(-0.866025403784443,0.,-0.499999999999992));
#1582=DIRECTION('',(-0.499999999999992,0.,0.866025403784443));
#1583=AXIS2_PLACEMENT_3D('',#1580,#1581,#1582);
#1584=PLANE('',#1583);
#1585=ORIENTED_EDGE('',*,*,#198,.F.);
#1586=ORIENTED_EDGE('',*,*,#1575,.F.);
#1587=ORIENTED_EDGE('',*,*,#225,.F.);
#1588=ORIENTED_EDGE('',*,*,#164,.F.);
#1589=EDGE_LOOP('',(#1585,#1586,#1587,#1588));
#1590=FACE_BOUND('',#1589,.T.);
#1591=ADVANCED_FACE('F737',(#1590),#1584,.T.);
#1592=CARTESIAN_POINT('',(-1.08253175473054,8.00000000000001,3.87500000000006));
#1593=DIRECTION('',(-0.866025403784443,0.,-0.499999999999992));
#1594=DIRECTION('',(-0.499999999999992,0.,0.866025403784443));
#1595=AXIS2_PLACEMENT_3D('',#1592,#1593,#1594);
#1596=PLANE('',#1595);
#1597=ORIENTED_EDGE('',*,*,#1567,.T.);
#1598=ORIENTED_EDGE('',*,*,#270,.T.);
#1599=ORIENTED_EDGE('',*,*,#245,.T.);
#1600=ORIENTED_EDGE('',*,*,#309,.T.);
#1601=EDGE_LOOP('',(#1597,#1598,#1599,#1600));
#1602=FACE_BOUND('',#1601,.T.);
#1603=ADVANCED_FACE('F725',(#1602),#1596,.F.);
#1604=CARTESIAN_POINT('',(-8.50000000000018,16.,-14.7224318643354));
#1605=DIRECTION('',(-0.336336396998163,-0.739940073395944,-0.582551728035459));
#1606=DIRECTION('',(0.369970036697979,-0.672672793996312,0.640806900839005));
#1607=AXIS2_PLACEMENT_3D('',#1604,#1605,#1606);
#1608=PLANE('',#1607);
#1609=ORIENTED_EDGE('',*,*,#33,.F.);
#1610=ORIENTED_EDGE('',*,*,#179,.F.);
#1611=DIRECTION('',(0.369970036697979,-0.672672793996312,0.640806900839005));
#1612=VECTOR('',#1611,1.);
#1613=CARTESIAN_POINT('',(-7.63397459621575,16.,-15.2224318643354));
#1614=LINE('',#1613,#1612);
#1615=EDGE_CURVE('E332',#209,#176,#1614,.T.);
#1616=ORIENTED_EDGE('',*,*,#1615,.F.);
#1617=ORIENTED_EDGE('',*,*,#210,.F.);
#1618=ORIENTED_EDGE('',*,*,#110,.F.);
#1619=DIRECTION('',(0.369970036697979,-0.672672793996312,0.640806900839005));
#1620=VECTOR('',#1619,1.);
#1621=CARTESIAN_POINT('',(-9.36602540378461,16.,-14.2224318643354));
#1622=LINE('',#1621,#1620);
#1623=EDGE_CURVE('E329',#100,#32,#1622,.T.);
#1624=ORIENTED_EDGE('',*,*,#1623,.T.);
#1625=EDGE_LOOP('',(#1609,#1610,#1616,#1617,#1618,#1624));
#1626=FACE_BOUND('',#1625,.T.);
#1627=ADVANCED_FACE('F818',(#1626),#1608,.F.);
#1628=CARTESIAN_POINT('',(1.08253175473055,8.00000000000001,3.87499999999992));
#1629=DIRECTION('',(-0.866025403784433,0.,0.50000000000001));
#1630=DIRECTION('',(0.50000000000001,0.,0.866025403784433));
#1631=AXIS2_PLACEMENT_3D('',#1628,#1629,#1630);
#1632=PLANE('',#1631);
#1633=ORIENTED_EDGE('',*,*,#41,.F.);
#1634=ORIENTED_EDGE('',*,*,#1623,.F.);
#1635=ORIENTED_EDGE('',*,*,#101,.F.);
#1636=ORIENTED_EDGE('',*,*,#837,.F.);
#1637=EDGE_LOOP('',(#1633,#1634,#1635,#1636));
#1638=FACE_BOUND('',#1637,.T.);
#1639=ADVANCED_FACE('F823',(#1638),#1632,.T.);
#1640=CARTESIAN_POINT('',(2.81458256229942,8.00000000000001,2.8749999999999));
#1641=DIRECTION('',(-0.866025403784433,0.,0.50000000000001));
#1642=DIRECTION('',(0.50000000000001,0.,0.866025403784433));
#1643=AXIS2_PLACEMENT_3D('',#1640,#1641,#1642);
#1644=PLANE('',#1643);
#1645=ORIENTED_EDGE('',*,*,#1615,.T.);
#1646=ORIENTED_EDGE('',*,*,#177,.T.);
#1647=ORIENTED_EDGE('',*,*,#152,.T.);
#1648=ORIENTED_EDGE('',*,*,#216,.T.);
#1649=EDGE_LOOP('',(#1645,#1646,#1647,#1648));
#1650=FACE_BOUND('',#1649,.T.);
#1651=ADVANCED_FACE('F328',(#1650),#1644,.F.);
#1652=CLOSED_SHELL('',(#78,#138,#170,#203,#236,#263,#296,#329,#356,#389,#422,#449,#482,#509,
#542,#686,#718,#740,#768,#788,#806,#831,#848,#874,#899,#919,#1040,#1057,#1069,#1086,#1103,#1115,
#1135,#1155,#1167,#1184,#1201,#1213,#1230,#1247,#1259,#1279,#1299,#1311,#1331,#1351,#1363,#1387,
#1399,#1411,#1435,#1447,#1459,#1483,#1495,#1507,#1531,#1543,#1555,#1579,#1591,#1603,#1627,#1639,#1651));
#1653=MANIFOLD_SOLID_BREP('B2',#1652);
#1654=ADVANCED_BREP_SHAPE_REPRESENTATION('',(#18,#1653),#14);
#1655=SHAPE_DEFINITION_REPRESENTATION(#9,#1654);
ENDSEC;
END-ISO-10303-21;
